##
## LEF for PtnCells ;
## created by Innovus v15.23-s045_1 on Mon Mar 16 21:43:37 2026
##

VERSION 5.8 ;

BUSBITCHARS "[]" ;
DIVIDERCHAR "/" ;

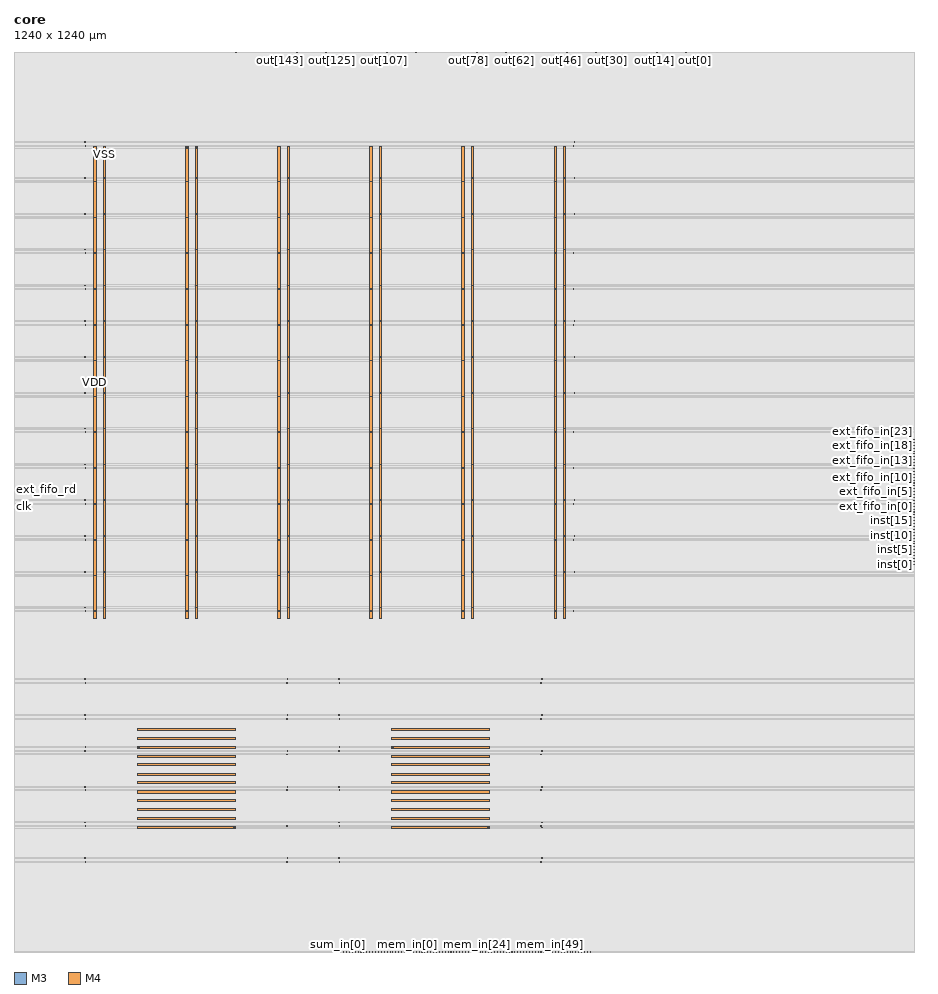
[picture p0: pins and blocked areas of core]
MACRO core
  CLASS BLOCK ;
  SIZE 1240.0000 BY 1240.0000 ;
  FOREIGN core 0.0000 0.0000 ;
  ORIGIN 0 0 ;
  SYMMETRY X Y R90 ;
  PIN clk
    DIRECTION INPUT ;
    USE SIGNAL ;
    PORT
      LAYER M3 ;
        RECT 0.0000 613.7500 0.5200 613.8500 ;
    END
  END clk
  PIN sum_in[23]
    DIRECTION INPUT ;
    USE SIGNAL ;
    PORT
      LAYER M4 ;
        RECT 538.0500 0.0000 538.1500 0.5200 ;
    END
  END sum_in[23]
  PIN sum_in[22]
    DIRECTION INPUT ;
    USE SIGNAL ;
    PORT
      LAYER M4 ;
        RECT 534.0500 0.0000 534.1500 0.5200 ;
    END
  END sum_in[22]
  PIN sum_in[21]
    DIRECTION INPUT ;
    USE SIGNAL ;
    PORT
      LAYER M4 ;
        RECT 530.0500 0.0000 530.1500 0.5200 ;
    END
  END sum_in[21]
  PIN sum_in[20]
    DIRECTION INPUT ;
    USE SIGNAL ;
    PORT
      LAYER M4 ;
        RECT 526.0500 0.0000 526.1500 0.5200 ;
    END
  END sum_in[20]
  PIN sum_in[19]
    DIRECTION INPUT ;
    USE SIGNAL ;
    PORT
      LAYER M4 ;
        RECT 522.0500 0.0000 522.1500 0.5200 ;
    END
  END sum_in[19]
  PIN sum_in[18]
    DIRECTION INPUT ;
    USE SIGNAL ;
    PORT
      LAYER M4 ;
        RECT 518.0500 0.0000 518.1500 0.5200 ;
    END
  END sum_in[18]
  PIN sum_in[17]
    DIRECTION INPUT ;
    USE SIGNAL ;
    PORT
      LAYER M4 ;
        RECT 514.0500 0.0000 514.1500 0.5200 ;
    END
  END sum_in[17]
  PIN sum_in[16]
    DIRECTION INPUT ;
    USE SIGNAL ;
    PORT
      LAYER M4 ;
        RECT 510.0500 0.0000 510.1500 0.5200 ;
    END
  END sum_in[16]
  PIN sum_in[15]
    DIRECTION INPUT ;
    USE SIGNAL ;
    PORT
      LAYER M4 ;
        RECT 506.0500 0.0000 506.1500 0.5200 ;
    END
  END sum_in[15]
  PIN sum_in[14]
    DIRECTION INPUT ;
    USE SIGNAL ;
    PORT
      LAYER M4 ;
        RECT 502.0500 0.0000 502.1500 0.5200 ;
    END
  END sum_in[14]
  PIN sum_in[13]
    DIRECTION INPUT ;
    USE SIGNAL ;
    PORT
      LAYER M4 ;
        RECT 498.0500 0.0000 498.1500 0.5200 ;
    END
  END sum_in[13]
  PIN sum_in[12]
    DIRECTION INPUT ;
    USE SIGNAL ;
    PORT
      LAYER M4 ;
        RECT 494.0500 0.0000 494.1500 0.5200 ;
    END
  END sum_in[12]
  PIN sum_in[11]
    DIRECTION INPUT ;
    USE SIGNAL ;
    PORT
      LAYER M4 ;
        RECT 490.0500 0.0000 490.1500 0.5200 ;
    END
  END sum_in[11]
  PIN sum_in[10]
    DIRECTION INPUT ;
    USE SIGNAL ;
    PORT
      LAYER M4 ;
        RECT 486.0500 0.0000 486.1500 0.5200 ;
    END
  END sum_in[10]
  PIN sum_in[9]
    DIRECTION INPUT ;
    USE SIGNAL ;
    PORT
      LAYER M4 ;
        RECT 482.0500 0.0000 482.1500 0.5200 ;
    END
  END sum_in[9]
  PIN sum_in[8]
    DIRECTION INPUT ;
    USE SIGNAL ;
    PORT
      LAYER M4 ;
        RECT 478.0500 0.0000 478.1500 0.5200 ;
    END
  END sum_in[8]
  PIN sum_in[7]
    DIRECTION INPUT ;
    USE SIGNAL ;
    PORT
      LAYER M4 ;
        RECT 474.0500 0.0000 474.1500 0.5200 ;
    END
  END sum_in[7]
  PIN sum_in[6]
    DIRECTION INPUT ;
    USE SIGNAL ;
    PORT
      LAYER M4 ;
        RECT 470.0500 0.0000 470.1500 0.5200 ;
    END
  END sum_in[6]
  PIN sum_in[5]
    DIRECTION INPUT ;
    USE SIGNAL ;
    PORT
      LAYER M4 ;
        RECT 466.0500 0.0000 466.1500 0.5200 ;
    END
  END sum_in[5]
  PIN sum_in[4]
    DIRECTION INPUT ;
    USE SIGNAL ;
    PORT
      LAYER M4 ;
        RECT 462.0500 0.0000 462.1500 0.5200 ;
    END
  END sum_in[4]
  PIN sum_in[3]
    DIRECTION INPUT ;
    USE SIGNAL ;
    PORT
      LAYER M4 ;
        RECT 458.0500 0.0000 458.1500 0.5200 ;
    END
  END sum_in[3]
  PIN sum_in[2]
    DIRECTION INPUT ;
    USE SIGNAL ;
    PORT
      LAYER M4 ;
        RECT 454.0500 0.0000 454.1500 0.5200 ;
    END
  END sum_in[2]
  PIN sum_in[1]
    DIRECTION INPUT ;
    USE SIGNAL ;
    PORT
      LAYER M4 ;
        RECT 450.0500 0.0000 450.1500 0.5200 ;
    END
  END sum_in[1]
  PIN sum_in[0]
    DIRECTION INPUT ;
    USE SIGNAL ;
    PORT
      LAYER M4 ;
        RECT 446.0500 0.0000 446.1500 0.5200 ;
    END
  END sum_in[0]
  PIN mem_in[63]
    DIRECTION INPUT ;
    USE SIGNAL ;
    PORT
      LAYER M4 ;
        RECT 794.0500 0.0000 794.1500 0.5200 ;
    END
  END mem_in[63]
  PIN mem_in[62]
    DIRECTION INPUT ;
    USE SIGNAL ;
    PORT
      LAYER M4 ;
        RECT 790.0500 0.0000 790.1500 0.5200 ;
    END
  END mem_in[62]
  PIN mem_in[61]
    DIRECTION INPUT ;
    USE SIGNAL ;
    PORT
      LAYER M4 ;
        RECT 786.0500 0.0000 786.1500 0.5200 ;
    END
  END mem_in[61]
  PIN mem_in[60]
    DIRECTION INPUT ;
    USE SIGNAL ;
    PORT
      LAYER M4 ;
        RECT 782.0500 0.0000 782.1500 0.5200 ;
    END
  END mem_in[60]
  PIN mem_in[59]
    DIRECTION INPUT ;
    USE SIGNAL ;
    PORT
      LAYER M4 ;
        RECT 778.0500 0.0000 778.1500 0.5200 ;
    END
  END mem_in[59]
  PIN mem_in[58]
    DIRECTION INPUT ;
    USE SIGNAL ;
    PORT
      LAYER M4 ;
        RECT 774.0500 0.0000 774.1500 0.5200 ;
    END
  END mem_in[58]
  PIN mem_in[57]
    DIRECTION INPUT ;
    USE SIGNAL ;
    PORT
      LAYER M4 ;
        RECT 770.0500 0.0000 770.1500 0.5200 ;
    END
  END mem_in[57]
  PIN mem_in[56]
    DIRECTION INPUT ;
    USE SIGNAL ;
    PORT
      LAYER M4 ;
        RECT 766.0500 0.0000 766.1500 0.5200 ;
    END
  END mem_in[56]
  PIN mem_in[55]
    DIRECTION INPUT ;
    USE SIGNAL ;
    PORT
      LAYER M4 ;
        RECT 762.0500 0.0000 762.1500 0.5200 ;
    END
  END mem_in[55]
  PIN mem_in[54]
    DIRECTION INPUT ;
    USE SIGNAL ;
    PORT
      LAYER M4 ;
        RECT 758.0500 0.0000 758.1500 0.5200 ;
    END
  END mem_in[54]
  PIN mem_in[53]
    DIRECTION INPUT ;
    USE SIGNAL ;
    PORT
      LAYER M4 ;
        RECT 754.0500 0.0000 754.1500 0.5200 ;
    END
  END mem_in[53]
  PIN mem_in[52]
    DIRECTION INPUT ;
    USE SIGNAL ;
    PORT
      LAYER M4 ;
        RECT 750.0500 0.0000 750.1500 0.5200 ;
    END
  END mem_in[52]
  PIN mem_in[51]
    DIRECTION INPUT ;
    USE SIGNAL ;
    PORT
      LAYER M4 ;
        RECT 746.0500 0.0000 746.1500 0.5200 ;
    END
  END mem_in[51]
  PIN mem_in[50]
    DIRECTION INPUT ;
    USE SIGNAL ;
    PORT
      LAYER M4 ;
        RECT 742.0500 0.0000 742.1500 0.5200 ;
    END
  END mem_in[50]
  PIN mem_in[49]
    DIRECTION INPUT ;
    USE SIGNAL ;
    PORT
      LAYER M4 ;
        RECT 738.0500 0.0000 738.1500 0.5200 ;
    END
  END mem_in[49]
  PIN mem_in[48]
    DIRECTION INPUT ;
    USE SIGNAL ;
    PORT
      LAYER M4 ;
        RECT 734.0500 0.0000 734.1500 0.5200 ;
    END
  END mem_in[48]
  PIN mem_in[47]
    DIRECTION INPUT ;
    USE SIGNAL ;
    PORT
      LAYER M4 ;
        RECT 730.0500 0.0000 730.1500 0.5200 ;
    END
  END mem_in[47]
  PIN mem_in[46]
    DIRECTION INPUT ;
    USE SIGNAL ;
    PORT
      LAYER M4 ;
        RECT 726.0500 0.0000 726.1500 0.5200 ;
    END
  END mem_in[46]
  PIN mem_in[45]
    DIRECTION INPUT ;
    USE SIGNAL ;
    PORT
      LAYER M4 ;
        RECT 722.0500 0.0000 722.1500 0.5200 ;
    END
  END mem_in[45]
  PIN mem_in[44]
    DIRECTION INPUT ;
    USE SIGNAL ;
    PORT
      LAYER M4 ;
        RECT 718.0500 0.0000 718.1500 0.5200 ;
    END
  END mem_in[44]
  PIN mem_in[43]
    DIRECTION INPUT ;
    USE SIGNAL ;
    PORT
      LAYER M4 ;
        RECT 714.0500 0.0000 714.1500 0.5200 ;
    END
  END mem_in[43]
  PIN mem_in[42]
    DIRECTION INPUT ;
    USE SIGNAL ;
    PORT
      LAYER M4 ;
        RECT 710.0500 0.0000 710.1500 0.5200 ;
    END
  END mem_in[42]
  PIN mem_in[41]
    DIRECTION INPUT ;
    USE SIGNAL ;
    PORT
      LAYER M4 ;
        RECT 706.0500 0.0000 706.1500 0.5200 ;
    END
  END mem_in[41]
  PIN mem_in[40]
    DIRECTION INPUT ;
    USE SIGNAL ;
    PORT
      LAYER M4 ;
        RECT 702.0500 0.0000 702.1500 0.5200 ;
    END
  END mem_in[40]
  PIN mem_in[39]
    DIRECTION INPUT ;
    USE SIGNAL ;
    PORT
      LAYER M4 ;
        RECT 698.0500 0.0000 698.1500 0.5200 ;
    END
  END mem_in[39]
  PIN mem_in[38]
    DIRECTION INPUT ;
    USE SIGNAL ;
    PORT
      LAYER M4 ;
        RECT 694.0500 0.0000 694.1500 0.5200 ;
    END
  END mem_in[38]
  PIN mem_in[37]
    DIRECTION INPUT ;
    USE SIGNAL ;
    PORT
      LAYER M4 ;
        RECT 690.0500 0.0000 690.1500 0.5200 ;
    END
  END mem_in[37]
  PIN mem_in[36]
    DIRECTION INPUT ;
    USE SIGNAL ;
    PORT
      LAYER M4 ;
        RECT 686.0500 0.0000 686.1500 0.5200 ;
    END
  END mem_in[36]
  PIN mem_in[35]
    DIRECTION INPUT ;
    USE SIGNAL ;
    PORT
      LAYER M4 ;
        RECT 682.0500 0.0000 682.1500 0.5200 ;
    END
  END mem_in[35]
  PIN mem_in[34]
    DIRECTION INPUT ;
    USE SIGNAL ;
    PORT
      LAYER M4 ;
        RECT 678.0500 0.0000 678.1500 0.5200 ;
    END
  END mem_in[34]
  PIN mem_in[33]
    DIRECTION INPUT ;
    USE SIGNAL ;
    PORT
      LAYER M4 ;
        RECT 674.0500 0.0000 674.1500 0.5200 ;
    END
  END mem_in[33]
  PIN mem_in[32]
    DIRECTION INPUT ;
    USE SIGNAL ;
    PORT
      LAYER M4 ;
        RECT 670.0500 0.0000 670.1500 0.5200 ;
    END
  END mem_in[32]
  PIN mem_in[31]
    DIRECTION INPUT ;
    USE SIGNAL ;
    PORT
      LAYER M4 ;
        RECT 666.0500 0.0000 666.1500 0.5200 ;
    END
  END mem_in[31]
  PIN mem_in[30]
    DIRECTION INPUT ;
    USE SIGNAL ;
    PORT
      LAYER M4 ;
        RECT 662.0500 0.0000 662.1500 0.5200 ;
    END
  END mem_in[30]
  PIN mem_in[29]
    DIRECTION INPUT ;
    USE SIGNAL ;
    PORT
      LAYER M4 ;
        RECT 658.0500 0.0000 658.1500 0.5200 ;
    END
  END mem_in[29]
  PIN mem_in[28]
    DIRECTION INPUT ;
    USE SIGNAL ;
    PORT
      LAYER M4 ;
        RECT 654.0500 0.0000 654.1500 0.5200 ;
    END
  END mem_in[28]
  PIN mem_in[27]
    DIRECTION INPUT ;
    USE SIGNAL ;
    PORT
      LAYER M4 ;
        RECT 650.0500 0.0000 650.1500 0.5200 ;
    END
  END mem_in[27]
  PIN mem_in[26]
    DIRECTION INPUT ;
    USE SIGNAL ;
    PORT
      LAYER M4 ;
        RECT 646.0500 0.0000 646.1500 0.5200 ;
    END
  END mem_in[26]
  PIN mem_in[25]
    DIRECTION INPUT ;
    USE SIGNAL ;
    PORT
      LAYER M4 ;
        RECT 642.0500 0.0000 642.1500 0.5200 ;
    END
  END mem_in[25]
  PIN mem_in[24]
    DIRECTION INPUT ;
    USE SIGNAL ;
    PORT
      LAYER M4 ;
        RECT 638.0500 0.0000 638.1500 0.5200 ;
    END
  END mem_in[24]
  PIN mem_in[23]
    DIRECTION INPUT ;
    USE SIGNAL ;
    PORT
      LAYER M4 ;
        RECT 634.0500 0.0000 634.1500 0.5200 ;
    END
  END mem_in[23]
  PIN mem_in[22]
    DIRECTION INPUT ;
    USE SIGNAL ;
    PORT
      LAYER M4 ;
        RECT 630.0500 0.0000 630.1500 0.5200 ;
    END
  END mem_in[22]
  PIN mem_in[21]
    DIRECTION INPUT ;
    USE SIGNAL ;
    PORT
      LAYER M4 ;
        RECT 626.0500 0.0000 626.1500 0.5200 ;
    END
  END mem_in[21]
  PIN mem_in[20]
    DIRECTION INPUT ;
    USE SIGNAL ;
    PORT
      LAYER M4 ;
        RECT 622.0500 0.0000 622.1500 0.5200 ;
    END
  END mem_in[20]
  PIN mem_in[19]
    DIRECTION INPUT ;
    USE SIGNAL ;
    PORT
      LAYER M4 ;
        RECT 618.0500 0.0000 618.1500 0.5200 ;
    END
  END mem_in[19]
  PIN mem_in[18]
    DIRECTION INPUT ;
    USE SIGNAL ;
    PORT
      LAYER M4 ;
        RECT 614.0500 0.0000 614.1500 0.5200 ;
    END
  END mem_in[18]
  PIN mem_in[17]
    DIRECTION INPUT ;
    USE SIGNAL ;
    PORT
      LAYER M4 ;
        RECT 610.0500 0.0000 610.1500 0.5200 ;
    END
  END mem_in[17]
  PIN mem_in[16]
    DIRECTION INPUT ;
    USE SIGNAL ;
    PORT
      LAYER M4 ;
        RECT 606.0500 0.0000 606.1500 0.5200 ;
    END
  END mem_in[16]
  PIN mem_in[15]
    DIRECTION INPUT ;
    USE SIGNAL ;
    PORT
      LAYER M4 ;
        RECT 602.0500 0.0000 602.1500 0.5200 ;
    END
  END mem_in[15]
  PIN mem_in[14]
    DIRECTION INPUT ;
    USE SIGNAL ;
    PORT
      LAYER M4 ;
        RECT 598.0500 0.0000 598.1500 0.5200 ;
    END
  END mem_in[14]
  PIN mem_in[13]
    DIRECTION INPUT ;
    USE SIGNAL ;
    PORT
      LAYER M4 ;
        RECT 594.0500 0.0000 594.1500 0.5200 ;
    END
  END mem_in[13]
  PIN mem_in[12]
    DIRECTION INPUT ;
    USE SIGNAL ;
    PORT
      LAYER M4 ;
        RECT 590.0500 0.0000 590.1500 0.5200 ;
    END
  END mem_in[12]
  PIN mem_in[11]
    DIRECTION INPUT ;
    USE SIGNAL ;
    PORT
      LAYER M4 ;
        RECT 586.0500 0.0000 586.1500 0.5200 ;
    END
  END mem_in[11]
  PIN mem_in[10]
    DIRECTION INPUT ;
    USE SIGNAL ;
    PORT
      LAYER M4 ;
        RECT 582.0500 0.0000 582.1500 0.5200 ;
    END
  END mem_in[10]
  PIN mem_in[9]
    DIRECTION INPUT ;
    USE SIGNAL ;
    PORT
      LAYER M4 ;
        RECT 578.0500 0.0000 578.1500 0.5200 ;
    END
  END mem_in[9]
  PIN mem_in[8]
    DIRECTION INPUT ;
    USE SIGNAL ;
    PORT
      LAYER M4 ;
        RECT 574.0500 0.0000 574.1500 0.5200 ;
    END
  END mem_in[8]
  PIN mem_in[7]
    DIRECTION INPUT ;
    USE SIGNAL ;
    PORT
      LAYER M4 ;
        RECT 570.0500 0.0000 570.1500 0.5200 ;
    END
  END mem_in[7]
  PIN mem_in[6]
    DIRECTION INPUT ;
    USE SIGNAL ;
    PORT
      LAYER M4 ;
        RECT 566.0500 0.0000 566.1500 0.5200 ;
    END
  END mem_in[6]
  PIN mem_in[5]
    DIRECTION INPUT ;
    USE SIGNAL ;
    PORT
      LAYER M4 ;
        RECT 562.0500 0.0000 562.1500 0.5200 ;
    END
  END mem_in[5]
  PIN mem_in[4]
    DIRECTION INPUT ;
    USE SIGNAL ;
    PORT
      LAYER M4 ;
        RECT 558.0500 0.0000 558.1500 0.5200 ;
    END
  END mem_in[4]
  PIN mem_in[3]
    DIRECTION INPUT ;
    USE SIGNAL ;
    PORT
      LAYER M4 ;
        RECT 554.0500 0.0000 554.1500 0.5200 ;
    END
  END mem_in[3]
  PIN mem_in[2]
    DIRECTION INPUT ;
    USE SIGNAL ;
    PORT
      LAYER M4 ;
        RECT 550.0500 0.0000 550.1500 0.5200 ;
    END
  END mem_in[2]
  PIN mem_in[1]
    DIRECTION INPUT ;
    USE SIGNAL ;
    PORT
      LAYER M4 ;
        RECT 546.0500 0.0000 546.1500 0.5200 ;
    END
  END mem_in[1]
  PIN mem_in[0]
    DIRECTION INPUT ;
    USE SIGNAL ;
    PORT
      LAYER M4 ;
        RECT 542.0500 0.0000 542.1500 0.5200 ;
    END
  END mem_in[0]
  PIN out[159]
    DIRECTION OUTPUT ;
    USE SIGNAL ;
    PORT
      LAYER M4 ;
        RECT 301.8500 1239.4800 301.9500 1240.0000 ;
    END
  END out[159]
  PIN out[158]
    DIRECTION OUTPUT ;
    USE SIGNAL ;
    PORT
      LAYER M4 ;
        RECT 305.8500 1239.4800 305.9500 1240.0000 ;
    END
  END out[158]
  PIN out[157]
    DIRECTION OUTPUT ;
    USE SIGNAL ;
    PORT
      LAYER M4 ;
        RECT 309.8500 1239.4800 309.9500 1240.0000 ;
    END
  END out[157]
  PIN out[156]
    DIRECTION OUTPUT ;
    USE SIGNAL ;
    PORT
      LAYER M4 ;
        RECT 313.8500 1239.4800 313.9500 1240.0000 ;
    END
  END out[156]
  PIN out[155]
    DIRECTION OUTPUT ;
    USE SIGNAL ;
    PORT
      LAYER M4 ;
        RECT 317.8500 1239.4800 317.9500 1240.0000 ;
    END
  END out[155]
  PIN out[154]
    DIRECTION OUTPUT ;
    USE SIGNAL ;
    PORT
      LAYER M4 ;
        RECT 321.8500 1239.4800 321.9500 1240.0000 ;
    END
  END out[154]
  PIN out[153]
    DIRECTION OUTPUT ;
    USE SIGNAL ;
    PORT
      LAYER M4 ;
        RECT 325.8500 1239.4800 325.9500 1240.0000 ;
    END
  END out[153]
  PIN out[152]
    DIRECTION OUTPUT ;
    USE SIGNAL ;
    PORT
      LAYER M4 ;
        RECT 329.8500 1239.4800 329.9500 1240.0000 ;
    END
  END out[152]
  PIN out[151]
    DIRECTION OUTPUT ;
    USE SIGNAL ;
    PORT
      LAYER M4 ;
        RECT 333.8500 1239.4800 333.9500 1240.0000 ;
    END
  END out[151]
  PIN out[150]
    DIRECTION OUTPUT ;
    USE SIGNAL ;
    PORT
      LAYER M4 ;
        RECT 337.8500 1239.4800 337.9500 1240.0000 ;
    END
  END out[150]
  PIN out[149]
    DIRECTION OUTPUT ;
    USE SIGNAL ;
    PORT
      LAYER M4 ;
        RECT 341.8500 1239.4800 341.9500 1240.0000 ;
    END
  END out[149]
  PIN out[148]
    DIRECTION OUTPUT ;
    USE SIGNAL ;
    PORT
      LAYER M4 ;
        RECT 345.8500 1239.4800 345.9500 1240.0000 ;
    END
  END out[148]
  PIN out[147]
    DIRECTION OUTPUT ;
    USE SIGNAL ;
    PORT
      LAYER M4 ;
        RECT 349.8500 1239.4800 349.9500 1240.0000 ;
    END
  END out[147]
  PIN out[146]
    DIRECTION OUTPUT ;
    USE SIGNAL ;
    PORT
      LAYER M4 ;
        RECT 353.8500 1239.4800 353.9500 1240.0000 ;
    END
  END out[146]
  PIN out[145]
    DIRECTION OUTPUT ;
    USE SIGNAL ;
    PORT
      LAYER M4 ;
        RECT 357.8500 1239.4800 357.9500 1240.0000 ;
    END
  END out[145]
  PIN out[144]
    DIRECTION OUTPUT ;
    USE SIGNAL ;
    PORT
      LAYER M4 ;
        RECT 361.8500 1239.4800 361.9500 1240.0000 ;
    END
  END out[144]
  PIN out[143]
    DIRECTION OUTPUT ;
    USE SIGNAL ;
    PORT
      LAYER M4 ;
        RECT 365.8500 1239.4800 365.9500 1240.0000 ;
    END
  END out[143]
  PIN out[142]
    DIRECTION OUTPUT ;
    USE SIGNAL ;
    PORT
      LAYER M4 ;
        RECT 369.8500 1239.4800 369.9500 1240.0000 ;
    END
  END out[142]
  PIN out[141]
    DIRECTION OUTPUT ;
    USE SIGNAL ;
    PORT
      LAYER M4 ;
        RECT 373.8500 1239.4800 373.9500 1240.0000 ;
    END
  END out[141]
  PIN out[140]
    DIRECTION OUTPUT ;
    USE SIGNAL ;
    PORT
      LAYER M4 ;
        RECT 377.8500 1239.4800 377.9500 1240.0000 ;
    END
  END out[140]
  PIN out[139]
    DIRECTION OUTPUT ;
    USE SIGNAL ;
    PORT
      LAYER M4 ;
        RECT 381.8500 1239.4800 381.9500 1240.0000 ;
    END
  END out[139]
  PIN out[138]
    DIRECTION OUTPUT ;
    USE SIGNAL ;
    PORT
      LAYER M4 ;
        RECT 385.8500 1239.4800 385.9500 1240.0000 ;
    END
  END out[138]
  PIN out[137]
    DIRECTION OUTPUT ;
    USE SIGNAL ;
    PORT
      LAYER M4 ;
        RECT 389.8500 1239.4800 389.9500 1240.0000 ;
    END
  END out[137]
  PIN out[136]
    DIRECTION OUTPUT ;
    USE SIGNAL ;
    PORT
      LAYER M4 ;
        RECT 393.8500 1239.4800 393.9500 1240.0000 ;
    END
  END out[136]
  PIN out[135]
    DIRECTION OUTPUT ;
    USE SIGNAL ;
    PORT
      LAYER M4 ;
        RECT 397.8500 1239.4800 397.9500 1240.0000 ;
    END
  END out[135]
  PIN out[134]
    DIRECTION OUTPUT ;
    USE SIGNAL ;
    PORT
      LAYER M4 ;
        RECT 401.8500 1239.4800 401.9500 1240.0000 ;
    END
  END out[134]
  PIN out[133]
    DIRECTION OUTPUT ;
    USE SIGNAL ;
    PORT
      LAYER M4 ;
        RECT 405.8500 1239.4800 405.9500 1240.0000 ;
    END
  END out[133]
  PIN out[132]
    DIRECTION OUTPUT ;
    USE SIGNAL ;
    PORT
      LAYER M4 ;
        RECT 409.8500 1239.4800 409.9500 1240.0000 ;
    END
  END out[132]
  PIN out[131]
    DIRECTION OUTPUT ;
    USE SIGNAL ;
    PORT
      LAYER M4 ;
        RECT 413.8500 1239.4800 413.9500 1240.0000 ;
    END
  END out[131]
  PIN out[130]
    DIRECTION OUTPUT ;
    USE SIGNAL ;
    PORT
      LAYER M4 ;
        RECT 417.8500 1239.4800 417.9500 1240.0000 ;
    END
  END out[130]
  PIN out[129]
    DIRECTION OUTPUT ;
    USE SIGNAL ;
    PORT
      LAYER M4 ;
        RECT 421.8500 1239.4800 421.9500 1240.0000 ;
    END
  END out[129]
  PIN out[128]
    DIRECTION OUTPUT ;
    USE SIGNAL ;
    PORT
      LAYER M4 ;
        RECT 425.8500 1239.4800 425.9500 1240.0000 ;
    END
  END out[128]
  PIN out[127]
    DIRECTION OUTPUT ;
    USE SIGNAL ;
    PORT
      LAYER M4 ;
        RECT 429.8500 1239.4800 429.9500 1240.0000 ;
    END
  END out[127]
  PIN out[126]
    DIRECTION OUTPUT ;
    USE SIGNAL ;
    PORT
      LAYER M4 ;
        RECT 433.8500 1239.4800 433.9500 1240.0000 ;
    END
  END out[126]
  PIN out[125]
    DIRECTION OUTPUT ;
    USE SIGNAL ;
    PORT
      LAYER M4 ;
        RECT 437.8500 1239.4800 437.9500 1240.0000 ;
    END
  END out[125]
  PIN out[124]
    DIRECTION OUTPUT ;
    USE SIGNAL ;
    PORT
      LAYER M4 ;
        RECT 441.8500 1239.4800 441.9500 1240.0000 ;
    END
  END out[124]
  PIN out[123]
    DIRECTION OUTPUT ;
    USE SIGNAL ;
    PORT
      LAYER M4 ;
        RECT 445.8500 1239.4800 445.9500 1240.0000 ;
    END
  END out[123]
  PIN out[122]
    DIRECTION OUTPUT ;
    USE SIGNAL ;
    PORT
      LAYER M4 ;
        RECT 449.8500 1239.4800 449.9500 1240.0000 ;
    END
  END out[122]
  PIN out[121]
    DIRECTION OUTPUT ;
    USE SIGNAL ;
    PORT
      LAYER M4 ;
        RECT 453.8500 1239.4800 453.9500 1240.0000 ;
    END
  END out[121]
  PIN out[120]
    DIRECTION OUTPUT ;
    USE SIGNAL ;
    PORT
      LAYER M4 ;
        RECT 457.8500 1239.4800 457.9500 1240.0000 ;
    END
  END out[120]
  PIN out[119]
    DIRECTION OUTPUT ;
    USE SIGNAL ;
    PORT
      LAYER M4 ;
        RECT 461.8500 1239.4800 461.9500 1240.0000 ;
    END
  END out[119]
  PIN out[118]
    DIRECTION OUTPUT ;
    USE SIGNAL ;
    PORT
      LAYER M4 ;
        RECT 465.8500 1239.4800 465.9500 1240.0000 ;
    END
  END out[118]
  PIN out[117]
    DIRECTION OUTPUT ;
    USE SIGNAL ;
    PORT
      LAYER M4 ;
        RECT 469.8500 1239.4800 469.9500 1240.0000 ;
    END
  END out[117]
  PIN out[116]
    DIRECTION OUTPUT ;
    USE SIGNAL ;
    PORT
      LAYER M4 ;
        RECT 473.8500 1239.4800 473.9500 1240.0000 ;
    END
  END out[116]
  PIN out[115]
    DIRECTION OUTPUT ;
    USE SIGNAL ;
    PORT
      LAYER M4 ;
        RECT 477.8500 1239.4800 477.9500 1240.0000 ;
    END
  END out[115]
  PIN out[114]
    DIRECTION OUTPUT ;
    USE SIGNAL ;
    PORT
      LAYER M4 ;
        RECT 481.8500 1239.4800 481.9500 1240.0000 ;
    END
  END out[114]
  PIN out[113]
    DIRECTION OUTPUT ;
    USE SIGNAL ;
    PORT
      LAYER M4 ;
        RECT 485.8500 1239.4800 485.9500 1240.0000 ;
    END
  END out[113]
  PIN out[112]
    DIRECTION OUTPUT ;
    USE SIGNAL ;
    PORT
      LAYER M4 ;
        RECT 489.8500 1239.4800 489.9500 1240.0000 ;
    END
  END out[112]
  PIN out[111]
    DIRECTION OUTPUT ;
    USE SIGNAL ;
    PORT
      LAYER M4 ;
        RECT 493.8500 1239.4800 493.9500 1240.0000 ;
    END
  END out[111]
  PIN out[110]
    DIRECTION OUTPUT ;
    USE SIGNAL ;
    PORT
      LAYER M4 ;
        RECT 497.8500 1239.4800 497.9500 1240.0000 ;
    END
  END out[110]
  PIN out[109]
    DIRECTION OUTPUT ;
    USE SIGNAL ;
    PORT
      LAYER M4 ;
        RECT 501.8500 1239.4800 501.9500 1240.0000 ;
    END
  END out[109]
  PIN out[108]
    DIRECTION OUTPUT ;
    USE SIGNAL ;
    PORT
      LAYER M4 ;
        RECT 505.8500 1239.4800 505.9500 1240.0000 ;
    END
  END out[108]
  PIN out[107]
    DIRECTION OUTPUT ;
    USE SIGNAL ;
    PORT
      LAYER M4 ;
        RECT 509.8500 1239.4800 509.9500 1240.0000 ;
    END
  END out[107]
  PIN out[106]
    DIRECTION OUTPUT ;
    USE SIGNAL ;
    PORT
      LAYER M4 ;
        RECT 513.8500 1239.4800 513.9500 1240.0000 ;
    END
  END out[106]
  PIN out[105]
    DIRECTION OUTPUT ;
    USE SIGNAL ;
    PORT
      LAYER M4 ;
        RECT 517.8500 1239.4800 517.9500 1240.0000 ;
    END
  END out[105]
  PIN out[104]
    DIRECTION OUTPUT ;
    USE SIGNAL ;
    PORT
      LAYER M4 ;
        RECT 521.8500 1239.4800 521.9500 1240.0000 ;
    END
  END out[104]
  PIN out[103]
    DIRECTION OUTPUT ;
    USE SIGNAL ;
    PORT
      LAYER M4 ;
        RECT 525.8500 1239.4800 525.9500 1240.0000 ;
    END
  END out[103]
  PIN out[102]
    DIRECTION OUTPUT ;
    USE SIGNAL ;
    PORT
      LAYER M4 ;
        RECT 529.8500 1239.4800 529.9500 1240.0000 ;
    END
  END out[102]
  PIN out[101]
    DIRECTION OUTPUT ;
    USE SIGNAL ;
    PORT
      LAYER M4 ;
        RECT 533.8500 1239.4800 533.9500 1240.0000 ;
    END
  END out[101]
  PIN out[100]
    DIRECTION OUTPUT ;
    USE SIGNAL ;
    PORT
      LAYER M4 ;
        RECT 537.8500 1239.4800 537.9500 1240.0000 ;
    END
  END out[100]
  PIN out[99]
    DIRECTION OUTPUT ;
    USE SIGNAL ;
    PORT
      LAYER M4 ;
        RECT 541.8500 1239.4800 541.9500 1240.0000 ;
    END
  END out[99]
  PIN out[98]
    DIRECTION OUTPUT ;
    USE SIGNAL ;
    PORT
      LAYER M4 ;
        RECT 545.8500 1239.4800 545.9500 1240.0000 ;
    END
  END out[98]
  PIN out[97]
    DIRECTION OUTPUT ;
    USE SIGNAL ;
    PORT
      LAYER M4 ;
        RECT 549.8500 1239.4800 549.9500 1240.0000 ;
    END
  END out[97]
  PIN out[96]
    DIRECTION OUTPUT ;
    USE SIGNAL ;
    PORT
      LAYER M4 ;
        RECT 553.8500 1239.4800 553.9500 1240.0000 ;
    END
  END out[96]
  PIN out[95]
    DIRECTION OUTPUT ;
    USE SIGNAL ;
    PORT
      LAYER M4 ;
        RECT 557.8500 1239.4800 557.9500 1240.0000 ;
    END
  END out[95]
  PIN out[94]
    DIRECTION OUTPUT ;
    USE SIGNAL ;
    PORT
      LAYER M4 ;
        RECT 561.8500 1239.4800 561.9500 1240.0000 ;
    END
  END out[94]
  PIN out[93]
    DIRECTION OUTPUT ;
    USE SIGNAL ;
    PORT
      LAYER M4 ;
        RECT 565.8500 1239.4800 565.9500 1240.0000 ;
    END
  END out[93]
  PIN out[92]
    DIRECTION OUTPUT ;
    USE SIGNAL ;
    PORT
      LAYER M4 ;
        RECT 569.8500 1239.4800 569.9500 1240.0000 ;
    END
  END out[92]
  PIN out[91]
    DIRECTION OUTPUT ;
    USE SIGNAL ;
    PORT
      LAYER M4 ;
        RECT 573.8500 1239.4800 573.9500 1240.0000 ;
    END
  END out[91]
  PIN out[90]
    DIRECTION OUTPUT ;
    USE SIGNAL ;
    PORT
      LAYER M4 ;
        RECT 577.8500 1239.4800 577.9500 1240.0000 ;
    END
  END out[90]
  PIN out[89]
    DIRECTION OUTPUT ;
    USE SIGNAL ;
    PORT
      LAYER M4 ;
        RECT 581.8500 1239.4800 581.9500 1240.0000 ;
    END
  END out[89]
  PIN out[88]
    DIRECTION OUTPUT ;
    USE SIGNAL ;
    PORT
      LAYER M4 ;
        RECT 585.8500 1239.4800 585.9500 1240.0000 ;
    END
  END out[88]
  PIN out[87]
    DIRECTION OUTPUT ;
    USE SIGNAL ;
    PORT
      LAYER M4 ;
        RECT 589.8500 1239.4800 589.9500 1240.0000 ;
    END
  END out[87]
  PIN out[86]
    DIRECTION OUTPUT ;
    USE SIGNAL ;
    PORT
      LAYER M4 ;
        RECT 593.8500 1239.4800 593.9500 1240.0000 ;
    END
  END out[86]
  PIN out[85]
    DIRECTION OUTPUT ;
    USE SIGNAL ;
    PORT
      LAYER M4 ;
        RECT 597.8500 1239.4800 597.9500 1240.0000 ;
    END
  END out[85]
  PIN out[84]
    DIRECTION OUTPUT ;
    USE SIGNAL ;
    PORT
      LAYER M4 ;
        RECT 601.8500 1239.4800 601.9500 1240.0000 ;
    END
  END out[84]
  PIN out[83]
    DIRECTION OUTPUT ;
    USE SIGNAL ;
    PORT
      LAYER M4 ;
        RECT 605.8500 1239.4800 605.9500 1240.0000 ;
    END
  END out[83]
  PIN out[82]
    DIRECTION OUTPUT ;
    USE SIGNAL ;
    PORT
      LAYER M4 ;
        RECT 609.8500 1239.4800 609.9500 1240.0000 ;
    END
  END out[82]
  PIN out[81]
    DIRECTION OUTPUT ;
    USE SIGNAL ;
    PORT
      LAYER M4 ;
        RECT 613.8500 1239.4800 613.9500 1240.0000 ;
    END
  END out[81]
  PIN out[80]
    DIRECTION OUTPUT ;
    USE SIGNAL ;
    PORT
      LAYER M4 ;
        RECT 617.8500 1239.4800 617.9500 1240.0000 ;
    END
  END out[80]
  PIN out[79]
    DIRECTION OUTPUT ;
    USE SIGNAL ;
    PORT
      LAYER M4 ;
        RECT 621.8500 1239.4800 621.9500 1240.0000 ;
    END
  END out[79]
  PIN out[78]
    DIRECTION OUTPUT ;
    USE SIGNAL ;
    PORT
      LAYER M4 ;
        RECT 625.8500 1239.4800 625.9500 1240.0000 ;
    END
  END out[78]
  PIN out[77]
    DIRECTION OUTPUT ;
    USE SIGNAL ;
    PORT
      LAYER M4 ;
        RECT 629.8500 1239.4800 629.9500 1240.0000 ;
    END
  END out[77]
  PIN out[76]
    DIRECTION OUTPUT ;
    USE SIGNAL ;
    PORT
      LAYER M4 ;
        RECT 633.8500 1239.4800 633.9500 1240.0000 ;
    END
  END out[76]
  PIN out[75]
    DIRECTION OUTPUT ;
    USE SIGNAL ;
    PORT
      LAYER M4 ;
        RECT 637.8500 1239.4800 637.9500 1240.0000 ;
    END
  END out[75]
  PIN out[74]
    DIRECTION OUTPUT ;
    USE SIGNAL ;
    PORT
      LAYER M4 ;
        RECT 641.8500 1239.4800 641.9500 1240.0000 ;
    END
  END out[74]
  PIN out[73]
    DIRECTION OUTPUT ;
    USE SIGNAL ;
    PORT
      LAYER M4 ;
        RECT 645.8500 1239.4800 645.9500 1240.0000 ;
    END
  END out[73]
  PIN out[72]
    DIRECTION OUTPUT ;
    USE SIGNAL ;
    PORT
      LAYER M4 ;
        RECT 649.8500 1239.4800 649.9500 1240.0000 ;
    END
  END out[72]
  PIN out[71]
    DIRECTION OUTPUT ;
    USE SIGNAL ;
    PORT
      LAYER M4 ;
        RECT 653.8500 1239.4800 653.9500 1240.0000 ;
    END
  END out[71]
  PIN out[70]
    DIRECTION OUTPUT ;
    USE SIGNAL ;
    PORT
      LAYER M4 ;
        RECT 657.8500 1239.4800 657.9500 1240.0000 ;
    END
  END out[70]
  PIN out[69]
    DIRECTION OUTPUT ;
    USE SIGNAL ;
    PORT
      LAYER M4 ;
        RECT 661.8500 1239.4800 661.9500 1240.0000 ;
    END
  END out[69]
  PIN out[68]
    DIRECTION OUTPUT ;
    USE SIGNAL ;
    PORT
      LAYER M4 ;
        RECT 665.8500 1239.4800 665.9500 1240.0000 ;
    END
  END out[68]
  PIN out[67]
    DIRECTION OUTPUT ;
    USE SIGNAL ;
    PORT
      LAYER M4 ;
        RECT 669.8500 1239.4800 669.9500 1240.0000 ;
    END
  END out[67]
  PIN out[66]
    DIRECTION OUTPUT ;
    USE SIGNAL ;
    PORT
      LAYER M4 ;
        RECT 673.8500 1239.4800 673.9500 1240.0000 ;
    END
  END out[66]
  PIN out[65]
    DIRECTION OUTPUT ;
    USE SIGNAL ;
    PORT
      LAYER M4 ;
        RECT 677.8500 1239.4800 677.9500 1240.0000 ;
    END
  END out[65]
  PIN out[64]
    DIRECTION OUTPUT ;
    USE SIGNAL ;
    PORT
      LAYER M4 ;
        RECT 681.8500 1239.4800 681.9500 1240.0000 ;
    END
  END out[64]
  PIN out[63]
    DIRECTION OUTPUT ;
    USE SIGNAL ;
    PORT
      LAYER M4 ;
        RECT 685.8500 1239.4800 685.9500 1240.0000 ;
    END
  END out[63]
  PIN out[62]
    DIRECTION OUTPUT ;
    USE SIGNAL ;
    PORT
      LAYER M4 ;
        RECT 689.8500 1239.4800 689.9500 1240.0000 ;
    END
  END out[62]
  PIN out[61]
    DIRECTION OUTPUT ;
    USE SIGNAL ;
    PORT
      LAYER M4 ;
        RECT 693.8500 1239.4800 693.9500 1240.0000 ;
    END
  END out[61]
  PIN out[60]
    DIRECTION OUTPUT ;
    USE SIGNAL ;
    PORT
      LAYER M4 ;
        RECT 697.8500 1239.4800 697.9500 1240.0000 ;
    END
  END out[60]
  PIN out[59]
    DIRECTION OUTPUT ;
    USE SIGNAL ;
    PORT
      LAYER M4 ;
        RECT 701.8500 1239.4800 701.9500 1240.0000 ;
    END
  END out[59]
  PIN out[58]
    DIRECTION OUTPUT ;
    USE SIGNAL ;
    PORT
      LAYER M4 ;
        RECT 705.8500 1239.4800 705.9500 1240.0000 ;
    END
  END out[58]
  PIN out[57]
    DIRECTION OUTPUT ;
    USE SIGNAL ;
    PORT
      LAYER M4 ;
        RECT 709.8500 1239.4800 709.9500 1240.0000 ;
    END
  END out[57]
  PIN out[56]
    DIRECTION OUTPUT ;
    USE SIGNAL ;
    PORT
      LAYER M4 ;
        RECT 713.8500 1239.4800 713.9500 1240.0000 ;
    END
  END out[56]
  PIN out[55]
    DIRECTION OUTPUT ;
    USE SIGNAL ;
    PORT
      LAYER M4 ;
        RECT 717.8500 1239.4800 717.9500 1240.0000 ;
    END
  END out[55]
  PIN out[54]
    DIRECTION OUTPUT ;
    USE SIGNAL ;
    PORT
      LAYER M4 ;
        RECT 721.8500 1239.4800 721.9500 1240.0000 ;
    END
  END out[54]
  PIN out[53]
    DIRECTION OUTPUT ;
    USE SIGNAL ;
    PORT
      LAYER M4 ;
        RECT 725.8500 1239.4800 725.9500 1240.0000 ;
    END
  END out[53]
  PIN out[52]
    DIRECTION OUTPUT ;
    USE SIGNAL ;
    PORT
      LAYER M4 ;
        RECT 729.8500 1239.4800 729.9500 1240.0000 ;
    END
  END out[52]
  PIN out[51]
    DIRECTION OUTPUT ;
    USE SIGNAL ;
    PORT
      LAYER M4 ;
        RECT 733.8500 1239.4800 733.9500 1240.0000 ;
    END
  END out[51]
  PIN out[50]
    DIRECTION OUTPUT ;
    USE SIGNAL ;
    PORT
      LAYER M4 ;
        RECT 737.8500 1239.4800 737.9500 1240.0000 ;
    END
  END out[50]
  PIN out[49]
    DIRECTION OUTPUT ;
    USE SIGNAL ;
    PORT
      LAYER M4 ;
        RECT 741.8500 1239.4800 741.9500 1240.0000 ;
    END
  END out[49]
  PIN out[48]
    DIRECTION OUTPUT ;
    USE SIGNAL ;
    PORT
      LAYER M4 ;
        RECT 745.8500 1239.4800 745.9500 1240.0000 ;
    END
  END out[48]
  PIN out[47]
    DIRECTION OUTPUT ;
    USE SIGNAL ;
    PORT
      LAYER M4 ;
        RECT 749.8500 1239.4800 749.9500 1240.0000 ;
    END
  END out[47]
  PIN out[46]
    DIRECTION OUTPUT ;
    USE SIGNAL ;
    PORT
      LAYER M4 ;
        RECT 753.8500 1239.4800 753.9500 1240.0000 ;
    END
  END out[46]
  PIN out[45]
    DIRECTION OUTPUT ;
    USE SIGNAL ;
    PORT
      LAYER M4 ;
        RECT 757.8500 1239.4800 757.9500 1240.0000 ;
    END
  END out[45]
  PIN out[44]
    DIRECTION OUTPUT ;
    USE SIGNAL ;
    PORT
      LAYER M4 ;
        RECT 761.8500 1239.4800 761.9500 1240.0000 ;
    END
  END out[44]
  PIN out[43]
    DIRECTION OUTPUT ;
    USE SIGNAL ;
    PORT
      LAYER M4 ;
        RECT 765.8500 1239.4800 765.9500 1240.0000 ;
    END
  END out[43]
  PIN out[42]
    DIRECTION OUTPUT ;
    USE SIGNAL ;
    PORT
      LAYER M4 ;
        RECT 769.8500 1239.4800 769.9500 1240.0000 ;
    END
  END out[42]
  PIN out[41]
    DIRECTION OUTPUT ;
    USE SIGNAL ;
    PORT
      LAYER M4 ;
        RECT 773.8500 1239.4800 773.9500 1240.0000 ;
    END
  END out[41]
  PIN out[40]
    DIRECTION OUTPUT ;
    USE SIGNAL ;
    PORT
      LAYER M4 ;
        RECT 777.8500 1239.4800 777.9500 1240.0000 ;
    END
  END out[40]
  PIN out[39]
    DIRECTION OUTPUT ;
    USE SIGNAL ;
    PORT
      LAYER M4 ;
        RECT 781.8500 1239.4800 781.9500 1240.0000 ;
    END
  END out[39]
  PIN out[38]
    DIRECTION OUTPUT ;
    USE SIGNAL ;
    PORT
      LAYER M4 ;
        RECT 785.8500 1239.4800 785.9500 1240.0000 ;
    END
  END out[38]
  PIN out[37]
    DIRECTION OUTPUT ;
    USE SIGNAL ;
    PORT
      LAYER M4 ;
        RECT 789.8500 1239.4800 789.9500 1240.0000 ;
    END
  END out[37]
  PIN out[36]
    DIRECTION OUTPUT ;
    USE SIGNAL ;
    PORT
      LAYER M4 ;
        RECT 793.8500 1239.4800 793.9500 1240.0000 ;
    END
  END out[36]
  PIN out[35]
    DIRECTION OUTPUT ;
    USE SIGNAL ;
    PORT
      LAYER M4 ;
        RECT 797.8500 1239.4800 797.9500 1240.0000 ;
    END
  END out[35]
  PIN out[34]
    DIRECTION OUTPUT ;
    USE SIGNAL ;
    PORT
      LAYER M4 ;
        RECT 801.8500 1239.4800 801.9500 1240.0000 ;
    END
  END out[34]
  PIN out[33]
    DIRECTION OUTPUT ;
    USE SIGNAL ;
    PORT
      LAYER M4 ;
        RECT 805.8500 1239.4800 805.9500 1240.0000 ;
    END
  END out[33]
  PIN out[32]
    DIRECTION OUTPUT ;
    USE SIGNAL ;
    PORT
      LAYER M4 ;
        RECT 809.8500 1239.4800 809.9500 1240.0000 ;
    END
  END out[32]
  PIN out[31]
    DIRECTION OUTPUT ;
    USE SIGNAL ;
    PORT
      LAYER M4 ;
        RECT 813.8500 1239.4800 813.9500 1240.0000 ;
    END
  END out[31]
  PIN out[30]
    DIRECTION OUTPUT ;
    USE SIGNAL ;
    PORT
      LAYER M4 ;
        RECT 817.8500 1239.4800 817.9500 1240.0000 ;
    END
  END out[30]
  PIN out[29]
    DIRECTION OUTPUT ;
    USE SIGNAL ;
    PORT
      LAYER M4 ;
        RECT 821.8500 1239.4800 821.9500 1240.0000 ;
    END
  END out[29]
  PIN out[28]
    DIRECTION OUTPUT ;
    USE SIGNAL ;
    PORT
      LAYER M4 ;
        RECT 825.8500 1239.4800 825.9500 1240.0000 ;
    END
  END out[28]
  PIN out[27]
    DIRECTION OUTPUT ;
    USE SIGNAL ;
    PORT
      LAYER M4 ;
        RECT 829.8500 1239.4800 829.9500 1240.0000 ;
    END
  END out[27]
  PIN out[26]
    DIRECTION OUTPUT ;
    USE SIGNAL ;
    PORT
      LAYER M4 ;
        RECT 833.8500 1239.4800 833.9500 1240.0000 ;
    END
  END out[26]
  PIN out[25]
    DIRECTION OUTPUT ;
    USE SIGNAL ;
    PORT
      LAYER M4 ;
        RECT 837.8500 1239.4800 837.9500 1240.0000 ;
    END
  END out[25]
  PIN out[24]
    DIRECTION OUTPUT ;
    USE SIGNAL ;
    PORT
      LAYER M4 ;
        RECT 841.8500 1239.4800 841.9500 1240.0000 ;
    END
  END out[24]
  PIN out[23]
    DIRECTION OUTPUT ;
    USE SIGNAL ;
    PORT
      LAYER M4 ;
        RECT 845.8500 1239.4800 845.9500 1240.0000 ;
    END
  END out[23]
  PIN out[22]
    DIRECTION OUTPUT ;
    USE SIGNAL ;
    PORT
      LAYER M4 ;
        RECT 849.8500 1239.4800 849.9500 1240.0000 ;
    END
  END out[22]
  PIN out[21]
    DIRECTION OUTPUT ;
    USE SIGNAL ;
    PORT
      LAYER M4 ;
        RECT 853.8500 1239.4800 853.9500 1240.0000 ;
    END
  END out[21]
  PIN out[20]
    DIRECTION OUTPUT ;
    USE SIGNAL ;
    PORT
      LAYER M4 ;
        RECT 857.8500 1239.4800 857.9500 1240.0000 ;
    END
  END out[20]
  PIN out[19]
    DIRECTION OUTPUT ;
    USE SIGNAL ;
    PORT
      LAYER M4 ;
        RECT 861.8500 1239.4800 861.9500 1240.0000 ;
    END
  END out[19]
  PIN out[18]
    DIRECTION OUTPUT ;
    USE SIGNAL ;
    PORT
      LAYER M4 ;
        RECT 865.8500 1239.4800 865.9500 1240.0000 ;
    END
  END out[18]
  PIN out[17]
    DIRECTION OUTPUT ;
    USE SIGNAL ;
    PORT
      LAYER M4 ;
        RECT 869.8500 1239.4800 869.9500 1240.0000 ;
    END
  END out[17]
  PIN out[16]
    DIRECTION OUTPUT ;
    USE SIGNAL ;
    PORT
      LAYER M4 ;
        RECT 873.8500 1239.4800 873.9500 1240.0000 ;
    END
  END out[16]
  PIN out[15]
    DIRECTION OUTPUT ;
    USE SIGNAL ;
    PORT
      LAYER M4 ;
        RECT 877.8500 1239.4800 877.9500 1240.0000 ;
    END
  END out[15]
  PIN out[14]
    DIRECTION OUTPUT ;
    USE SIGNAL ;
    PORT
      LAYER M4 ;
        RECT 881.8500 1239.4800 881.9500 1240.0000 ;
    END
  END out[14]
  PIN out[13]
    DIRECTION OUTPUT ;
    USE SIGNAL ;
    PORT
      LAYER M4 ;
        RECT 885.8500 1239.4800 885.9500 1240.0000 ;
    END
  END out[13]
  PIN out[12]
    DIRECTION OUTPUT ;
    USE SIGNAL ;
    PORT
      LAYER M4 ;
        RECT 889.8500 1239.4800 889.9500 1240.0000 ;
    END
  END out[12]
  PIN out[11]
    DIRECTION OUTPUT ;
    USE SIGNAL ;
    PORT
      LAYER M4 ;
        RECT 893.8500 1239.4800 893.9500 1240.0000 ;
    END
  END out[11]
  PIN out[10]
    DIRECTION OUTPUT ;
    USE SIGNAL ;
    PORT
      LAYER M4 ;
        RECT 897.8500 1239.4800 897.9500 1240.0000 ;
    END
  END out[10]
  PIN out[9]
    DIRECTION OUTPUT ;
    USE SIGNAL ;
    PORT
      LAYER M4 ;
        RECT 901.8500 1239.4800 901.9500 1240.0000 ;
    END
  END out[9]
  PIN out[8]
    DIRECTION OUTPUT ;
    USE SIGNAL ;
    PORT
      LAYER M4 ;
        RECT 905.8500 1239.4800 905.9500 1240.0000 ;
    END
  END out[8]
  PIN out[7]
    DIRECTION OUTPUT ;
    USE SIGNAL ;
    PORT
      LAYER M4 ;
        RECT 909.8500 1239.4800 909.9500 1240.0000 ;
    END
  END out[7]
  PIN out[6]
    DIRECTION OUTPUT ;
    USE SIGNAL ;
    PORT
      LAYER M4 ;
        RECT 913.8500 1239.4800 913.9500 1240.0000 ;
    END
  END out[6]
  PIN out[5]
    DIRECTION OUTPUT ;
    USE SIGNAL ;
    PORT
      LAYER M4 ;
        RECT 917.8500 1239.4800 917.9500 1240.0000 ;
    END
  END out[5]
  PIN out[4]
    DIRECTION OUTPUT ;
    USE SIGNAL ;
    PORT
      LAYER M4 ;
        RECT 921.8500 1239.4800 921.9500 1240.0000 ;
    END
  END out[4]
  PIN out[3]
    DIRECTION OUTPUT ;
    USE SIGNAL ;
    PORT
      LAYER M4 ;
        RECT 925.8500 1239.4800 925.9500 1240.0000 ;
    END
  END out[3]
  PIN out[2]
    DIRECTION OUTPUT ;
    USE SIGNAL ;
    PORT
      LAYER M4 ;
        RECT 929.8500 1239.4800 929.9500 1240.0000 ;
    END
  END out[2]
  PIN out[1]
    DIRECTION OUTPUT ;
    USE SIGNAL ;
    PORT
      LAYER M4 ;
        RECT 933.8500 1239.4800 933.9500 1240.0000 ;
    END
  END out[1]
  PIN out[0]
    DIRECTION OUTPUT ;
    USE SIGNAL ;
    PORT
      LAYER M4 ;
        RECT 937.8500 1239.4800 937.9500 1240.0000 ;
    END
  END out[0]
  PIN inst[19]
    DIRECTION INPUT ;
    USE SIGNAL ;
    PORT
      LAYER M3 ;
        RECT 1239.4800 610.1500 1240.0000 610.2500 ;
    END
  END inst[19]
  PIN inst[18]
    DIRECTION INPUT ;
    USE SIGNAL ;
    PORT
      LAYER M3 ;
        RECT 1239.4800 606.1500 1240.0000 606.2500 ;
    END
  END inst[18]
  PIN inst[17]
    DIRECTION INPUT ;
    USE SIGNAL ;
    PORT
      LAYER M3 ;
        RECT 1239.4800 602.1500 1240.0000 602.2500 ;
    END
  END inst[17]
  PIN inst[16]
    DIRECTION INPUT ;
    USE SIGNAL ;
    PORT
      LAYER M3 ;
        RECT 1239.4800 598.1500 1240.0000 598.2500 ;
    END
  END inst[16]
  PIN inst[15]
    DIRECTION INPUT ;
    USE SIGNAL ;
    PORT
      LAYER M3 ;
        RECT 1239.4800 594.1500 1240.0000 594.2500 ;
    END
  END inst[15]
  PIN inst[14]
    DIRECTION INPUT ;
    USE SIGNAL ;
    PORT
      LAYER M3 ;
        RECT 1239.4800 590.1500 1240.0000 590.2500 ;
    END
  END inst[14]
  PIN inst[13]
    DIRECTION INPUT ;
    USE SIGNAL ;
    PORT
      LAYER M3 ;
        RECT 1239.4800 586.1500 1240.0000 586.2500 ;
    END
  END inst[13]
  PIN inst[12]
    DIRECTION INPUT ;
    USE SIGNAL ;
    PORT
      LAYER M3 ;
        RECT 1239.4800 582.1500 1240.0000 582.2500 ;
    END
  END inst[12]
  PIN inst[11]
    DIRECTION INPUT ;
    USE SIGNAL ;
    PORT
      LAYER M3 ;
        RECT 1239.4800 578.1500 1240.0000 578.2500 ;
    END
  END inst[11]
  PIN inst[10]
    DIRECTION INPUT ;
    USE SIGNAL ;
    PORT
      LAYER M3 ;
        RECT 1239.4800 574.1500 1240.0000 574.2500 ;
    END
  END inst[10]
  PIN inst[9]
    DIRECTION INPUT ;
    USE SIGNAL ;
    PORT
      LAYER M3 ;
        RECT 1239.4800 570.1500 1240.0000 570.2500 ;
    END
  END inst[9]
  PIN inst[8]
    DIRECTION INPUT ;
    USE SIGNAL ;
    PORT
      LAYER M3 ;
        RECT 1239.4800 566.1500 1240.0000 566.2500 ;
    END
  END inst[8]
  PIN inst[7]
    DIRECTION INPUT ;
    USE SIGNAL ;
    PORT
      LAYER M3 ;
        RECT 1239.4800 562.1500 1240.0000 562.2500 ;
    END
  END inst[7]
  PIN inst[6]
    DIRECTION INPUT ;
    USE SIGNAL ;
    PORT
      LAYER M3 ;
        RECT 1239.4800 558.1500 1240.0000 558.2500 ;
    END
  END inst[6]
  PIN inst[5]
    DIRECTION INPUT ;
    USE SIGNAL ;
    PORT
      LAYER M3 ;
        RECT 1239.4800 554.1500 1240.0000 554.2500 ;
    END
  END inst[5]
  PIN inst[4]
    DIRECTION INPUT ;
    USE SIGNAL ;
    PORT
      LAYER M3 ;
        RECT 1239.4800 550.1500 1240.0000 550.2500 ;
    END
  END inst[4]
  PIN inst[3]
    DIRECTION INPUT ;
    USE SIGNAL ;
    PORT
      LAYER M3 ;
        RECT 1239.4800 546.1500 1240.0000 546.2500 ;
    END
  END inst[3]
  PIN inst[2]
    DIRECTION INPUT ;
    USE SIGNAL ;
    PORT
      LAYER M3 ;
        RECT 1239.4800 542.1500 1240.0000 542.2500 ;
    END
  END inst[2]
  PIN inst[1]
    DIRECTION INPUT ;
    USE SIGNAL ;
    PORT
      LAYER M3 ;
        RECT 1239.4800 538.1500 1240.0000 538.2500 ;
    END
  END inst[1]
  PIN inst[0]
    DIRECTION INPUT ;
    USE SIGNAL ;
    PORT
      LAYER M3 ;
        RECT 1239.4800 534.1500 1240.0000 534.2500 ;
    END
  END inst[0]
  PIN reset
    DIRECTION INPUT ;
    USE SIGNAL ;
    PORT
      LAYER M3 ;
        RECT 0.0000 617.7500 0.5200 617.8500 ;
    END
  END reset
  PIN ext_fifo_wr
    DIRECTION OUTPUT ;
    USE SIGNAL ;
    PORT
      LAYER M3 ;
        RECT 0.0000 621.7500 0.5200 621.8500 ;
    END
  END ext_fifo_wr
  PIN ext_fifo_in[23]
    DIRECTION OUTPUT ;
    USE SIGNAL ;
    PORT
      LAYER M3 ;
        RECT 1239.4800 706.1500 1240.0000 706.2500 ;
    END
  END ext_fifo_in[23]
  PIN ext_fifo_in[22]
    DIRECTION OUTPUT ;
    USE SIGNAL ;
    PORT
      LAYER M3 ;
        RECT 1239.4800 702.1500 1240.0000 702.2500 ;
    END
  END ext_fifo_in[22]
  PIN ext_fifo_in[21]
    DIRECTION OUTPUT ;
    USE SIGNAL ;
    PORT
      LAYER M3 ;
        RECT 1239.4800 698.1500 1240.0000 698.2500 ;
    END
  END ext_fifo_in[21]
  PIN ext_fifo_in[20]
    DIRECTION OUTPUT ;
    USE SIGNAL ;
    PORT
      LAYER M3 ;
        RECT 1239.4800 694.1500 1240.0000 694.2500 ;
    END
  END ext_fifo_in[20]
  PIN ext_fifo_in[19]
    DIRECTION OUTPUT ;
    USE SIGNAL ;
    PORT
      LAYER M3 ;
        RECT 1239.4800 690.1500 1240.0000 690.2500 ;
    END
  END ext_fifo_in[19]
  PIN ext_fifo_in[18]
    DIRECTION OUTPUT ;
    USE SIGNAL ;
    PORT
      LAYER M3 ;
        RECT 1239.4800 686.1500 1240.0000 686.2500 ;
    END
  END ext_fifo_in[18]
  PIN ext_fifo_in[17]
    DIRECTION OUTPUT ;
    USE SIGNAL ;
    PORT
      LAYER M3 ;
        RECT 1239.4800 682.1500 1240.0000 682.2500 ;
    END
  END ext_fifo_in[17]
  PIN ext_fifo_in[16]
    DIRECTION OUTPUT ;
    USE SIGNAL ;
    PORT
      LAYER M3 ;
        RECT 1239.4800 678.1500 1240.0000 678.2500 ;
    END
  END ext_fifo_in[16]
  PIN ext_fifo_in[15]
    DIRECTION OUTPUT ;
    USE SIGNAL ;
    PORT
      LAYER M3 ;
        RECT 1239.4800 674.1500 1240.0000 674.2500 ;
    END
  END ext_fifo_in[15]
  PIN ext_fifo_in[14]
    DIRECTION OUTPUT ;
    USE SIGNAL ;
    PORT
      LAYER M3 ;
        RECT 1239.4800 670.1500 1240.0000 670.2500 ;
    END
  END ext_fifo_in[14]
  PIN ext_fifo_in[13]
    DIRECTION OUTPUT ;
    USE SIGNAL ;
    PORT
      LAYER M3 ;
        RECT 1239.4800 666.1500 1240.0000 666.2500 ;
    END
  END ext_fifo_in[13]
  PIN ext_fifo_in[12]
    DIRECTION OUTPUT ;
    USE SIGNAL ;
    PORT
      LAYER M3 ;
        RECT 1239.4800 662.1500 1240.0000 662.2500 ;
    END
  END ext_fifo_in[12]
  PIN ext_fifo_in[11]
    DIRECTION OUTPUT ;
    USE SIGNAL ;
    PORT
      LAYER M3 ;
        RECT 1239.4800 658.1500 1240.0000 658.2500 ;
    END
  END ext_fifo_in[11]
  PIN ext_fifo_in[10]
    DIRECTION OUTPUT ;
    USE SIGNAL ;
    PORT
      LAYER M3 ;
        RECT 1239.4800 654.1500 1240.0000 654.2500 ;
    END
  END ext_fifo_in[10]
  PIN ext_fifo_in[9]
    DIRECTION OUTPUT ;
    USE SIGNAL ;
    PORT
      LAYER M3 ;
        RECT 1239.4800 650.1500 1240.0000 650.2500 ;
    END
  END ext_fifo_in[9]
  PIN ext_fifo_in[8]
    DIRECTION OUTPUT ;
    USE SIGNAL ;
    PORT
      LAYER M3 ;
        RECT 1239.4800 646.1500 1240.0000 646.2500 ;
    END
  END ext_fifo_in[8]
  PIN ext_fifo_in[7]
    DIRECTION OUTPUT ;
    USE SIGNAL ;
    PORT
      LAYER M3 ;
        RECT 1239.4800 642.1500 1240.0000 642.2500 ;
    END
  END ext_fifo_in[7]
  PIN ext_fifo_in[6]
    DIRECTION OUTPUT ;
    USE SIGNAL ;
    PORT
      LAYER M3 ;
        RECT 1239.4800 638.1500 1240.0000 638.2500 ;
    END
  END ext_fifo_in[6]
  PIN ext_fifo_in[5]
    DIRECTION OUTPUT ;
    USE SIGNAL ;
    PORT
      LAYER M3 ;
        RECT 1239.4800 634.1500 1240.0000 634.2500 ;
    END
  END ext_fifo_in[5]
  PIN ext_fifo_in[4]
    DIRECTION OUTPUT ;
    USE SIGNAL ;
    PORT
      LAYER M3 ;
        RECT 1239.4800 630.1500 1240.0000 630.2500 ;
    END
  END ext_fifo_in[4]
  PIN ext_fifo_in[3]
    DIRECTION OUTPUT ;
    USE SIGNAL ;
    PORT
      LAYER M3 ;
        RECT 1239.4800 626.1500 1240.0000 626.2500 ;
    END
  END ext_fifo_in[3]
  PIN ext_fifo_in[2]
    DIRECTION OUTPUT ;
    USE SIGNAL ;
    PORT
      LAYER M3 ;
        RECT 1239.4800 622.1500 1240.0000 622.2500 ;
    END
  END ext_fifo_in[2]
  PIN ext_fifo_in[1]
    DIRECTION OUTPUT ;
    USE SIGNAL ;
    PORT
      LAYER M3 ;
        RECT 1239.4800 618.1500 1240.0000 618.2500 ;
    END
  END ext_fifo_in[1]
  PIN ext_fifo_in[0]
    DIRECTION OUTPUT ;
    USE SIGNAL ;
    PORT
      LAYER M3 ;
        RECT 1239.4800 614.1500 1240.0000 614.2500 ;
    END
  END ext_fifo_in[0]
  PIN ext_fifo_rd
    DIRECTION OUTPUT ;
    USE SIGNAL ;
    PORT
      LAYER M3 ;
        RECT 0.0000 625.7500 0.5200 625.8500 ;
    END
  END ext_fifo_rd
  PIN VSS
    DIRECTION INOUT ;
    USE GROUND ;

# P/G power stripe data as pin
    PORT
      LAYER M4 ;
        RECT 97.5000 128.6600 98.0000 129.6600 ;
        RECT 97.5000 177.9900 98.0000 178.9900 ;
        RECT 97.5000 227.3200 98.0000 228.3200 ;
        RECT 97.5000 276.6500 98.0000 277.6500 ;
        RECT 302.1650 171.2500 305.1650 171.7500 ;
        RECT 377.0000 128.6600 377.5000 129.6600 ;
        RECT 447.5000 128.6600 448.0000 129.6600 ;
        RECT 377.0000 171.2500 377.5000 171.7500 ;
        RECT 377.0000 177.9900 377.5000 178.9900 ;
        RECT 377.0000 227.3200 377.5000 228.3200 ;
        RECT 447.5000 177.9900 448.0000 178.9900 ;
        RECT 447.5000 227.3200 448.0000 228.3200 ;
        RECT 377.0000 276.6500 377.5000 277.6500 ;
        RECT 447.5000 276.6500 448.0000 277.6500 ;
        RECT 97.5000 325.9800 98.0000 326.9800 ;
        RECT 97.5000 375.3100 98.0000 376.3100 ;
        RECT 97.5000 473.9700 98.0000 474.9700 ;
        RECT 123.0000 473.9700 126.0000 474.9700 ;
        RECT 97.5000 523.3000 98.0000 524.3000 ;
        RECT 123.0000 523.3000 126.0000 524.3000 ;
        RECT 97.5000 572.6300 98.0000 573.6300 ;
        RECT 123.0000 572.6300 126.0000 573.6300 ;
        RECT 249.8000 473.9700 252.8000 474.9700 ;
        RECT 249.8000 523.3000 252.8000 524.3000 ;
        RECT 249.8000 572.6300 252.8000 573.6300 ;
        RECT 377.0000 325.9800 377.5000 326.9800 ;
        RECT 377.0000 375.3100 377.5000 376.3100 ;
        RECT 447.5000 325.9800 448.0000 326.9800 ;
        RECT 447.5000 375.3100 448.0000 376.3100 ;
        RECT 376.6000 473.9700 379.6000 474.9700 ;
        RECT 503.4000 473.9700 506.4000 474.9700 ;
        RECT 376.6000 523.3000 379.6000 524.3000 ;
        RECT 503.4000 523.3000 506.4000 524.3000 ;
        RECT 376.6000 572.6300 379.6000 573.6300 ;
        RECT 503.4000 572.6300 506.4000 573.6300 ;
        RECT 727.0000 128.6600 727.5000 129.6600 ;
        RECT 652.1650 171.2500 655.1650 171.7500 ;
        RECT 727.0000 171.2500 727.5000 171.7500 ;
        RECT 727.0000 177.9900 727.5000 178.9900 ;
        RECT 727.0000 227.3200 727.5000 228.3200 ;
        RECT 727.0000 276.6500 727.5000 277.6500 ;
        RECT 727.0000 325.9800 727.5000 326.9800 ;
        RECT 727.0000 375.3100 727.5000 376.3100 ;
        RECT 630.2000 473.9700 633.2000 474.9700 ;
        RECT 630.2000 523.3000 633.2000 524.3000 ;
        RECT 757.0000 473.9700 760.0000 474.9700 ;
        RECT 772.0000 473.9700 772.5000 474.9700 ;
        RECT 772.0000 523.3000 772.5000 524.3000 ;
        RECT 757.0000 523.3000 760.0000 524.3000 ;
        RECT 630.2000 572.6300 633.2000 573.6300 ;
        RECT 772.0000 572.6300 772.5000 573.6300 ;
        RECT 757.0000 572.6300 760.0000 573.6300 ;
        RECT 97.5000 621.9600 98.0000 622.9600 ;
        RECT 123.0000 621.9600 126.0000 622.9600 ;
        RECT 97.5000 671.2900 98.0000 672.2900 ;
        RECT 123.0000 671.2900 126.0000 672.2900 ;
        RECT 97.5000 720.6200 98.0000 721.6200 ;
        RECT 123.0000 720.6200 126.0000 721.6200 ;
        RECT 97.5000 769.9500 98.0000 770.9500 ;
        RECT 123.0000 769.9500 126.0000 770.9500 ;
        RECT 249.8000 621.9600 252.8000 622.9600 ;
        RECT 249.8000 671.2900 252.8000 672.2900 ;
        RECT 249.8000 720.6200 252.8000 721.6200 ;
        RECT 249.8000 769.9500 252.8000 770.9500 ;
        RECT 97.5000 819.2800 98.0000 820.2800 ;
        RECT 123.0000 819.2800 126.0000 820.2800 ;
        RECT 97.5000 868.6100 98.0000 869.6100 ;
        RECT 123.0000 868.6100 126.0000 869.6100 ;
        RECT 97.5000 917.9400 98.0000 918.9400 ;
        RECT 123.0000 917.9400 126.0000 918.9400 ;
        RECT 249.8000 819.2800 252.8000 820.2800 ;
        RECT 249.8000 868.6100 252.8000 869.6100 ;
        RECT 249.8000 917.9400 252.8000 918.9400 ;
        RECT 503.4000 671.2900 506.4000 672.2900 ;
        RECT 376.6000 671.2900 379.6000 672.2900 ;
        RECT 503.4000 621.9600 506.4000 622.9600 ;
        RECT 376.6000 621.9600 379.6000 622.9600 ;
        RECT 376.6000 720.6200 379.6000 721.6200 ;
        RECT 503.4000 720.6200 506.4000 721.6200 ;
        RECT 376.6000 769.9500 379.6000 770.9500 ;
        RECT 503.4000 769.9500 506.4000 770.9500 ;
        RECT 376.6000 819.2800 379.6000 820.2800 ;
        RECT 503.4000 819.2800 506.4000 820.2800 ;
        RECT 376.6000 868.6100 379.6000 869.6100 ;
        RECT 503.4000 868.6100 506.4000 869.6100 ;
        RECT 376.6000 917.9400 379.6000 918.9400 ;
        RECT 503.4000 917.9400 506.4000 918.9400 ;
        RECT 97.5000 967.2700 98.0000 968.2700 ;
        RECT 123.0000 967.2700 126.0000 968.2700 ;
        RECT 97.5000 1016.6000 98.0000 1017.6000 ;
        RECT 123.0000 1016.6000 126.0000 1017.6000 ;
        RECT 97.5000 1065.9300 98.0000 1066.9300 ;
        RECT 123.0000 1065.9300 126.0000 1066.9300 ;
        RECT 249.8000 967.2700 252.8000 968.2700 ;
        RECT 249.8000 1016.6000 252.8000 1017.6000 ;
        RECT 249.8000 1065.9300 252.8000 1066.9300 ;
        RECT 97.5000 1115.2600 98.0000 1116.2600 ;
        RECT 250.8000 1107.0000 251.8000 1110.0000 ;
        RECT 376.6000 967.2700 379.6000 968.2700 ;
        RECT 503.4000 967.2700 506.4000 968.2700 ;
        RECT 376.6000 1016.6000 379.6000 1017.6000 ;
        RECT 503.4000 1016.6000 506.4000 1017.6000 ;
        RECT 376.6000 1065.9300 379.6000 1066.9300 ;
        RECT 503.4000 1065.9300 506.4000 1066.9300 ;
        RECT 630.2000 621.9600 633.2000 622.9600 ;
        RECT 630.2000 671.2900 633.2000 672.2900 ;
        RECT 772.0000 621.9600 772.5000 622.9600 ;
        RECT 757.0000 621.9600 760.0000 622.9600 ;
        RECT 757.0000 671.2900 760.0000 672.2900 ;
        RECT 772.0000 671.2900 772.5000 672.2900 ;
        RECT 630.2000 720.6200 633.2000 721.6200 ;
        RECT 630.2000 769.9500 633.2000 770.9500 ;
        RECT 757.0000 720.6200 760.0000 721.6200 ;
        RECT 772.0000 720.6200 772.5000 721.6200 ;
        RECT 757.0000 769.9500 760.0000 770.9500 ;
        RECT 772.0000 769.9500 772.5000 770.9500 ;
        RECT 630.2000 819.2800 633.2000 820.2800 ;
        RECT 772.0000 819.2800 772.5000 820.2800 ;
        RECT 757.0000 819.2800 760.0000 820.2800 ;
        RECT 630.2000 868.6100 633.2000 869.6100 ;
        RECT 630.2000 917.9400 633.2000 918.9400 ;
        RECT 757.0000 868.6100 760.0000 869.6100 ;
        RECT 772.0000 868.6100 772.5000 869.6100 ;
        RECT 757.0000 917.9400 760.0000 918.9400 ;
        RECT 772.0000 917.9400 772.5000 918.9400 ;
        RECT 630.2000 967.2700 633.2000 968.2700 ;
        RECT 772.0000 967.2700 772.5000 968.2700 ;
        RECT 757.0000 967.2700 760.0000 968.2700 ;
        RECT 630.2000 1016.6000 633.2000 1017.6000 ;
        RECT 630.2000 1065.9300 633.2000 1066.9300 ;
        RECT 772.0000 1016.6000 772.5000 1017.6000 ;
        RECT 757.0000 1016.6000 760.0000 1017.6000 ;
        RECT 772.0000 1065.9300 772.5000 1066.9300 ;
        RECT 757.0000 1065.9300 760.0000 1066.9300 ;
        RECT 772.0000 1115.2600 772.5000 1116.2600 ;
    END
# end of P/G power stripe data as pin


# P/G pin shape extracted from block 'sram_w16'
    PORT
      LAYER M4 ;
        RECT 654.8350 170.0000 655.1650 173.0000 ;
        RECT 654.8350 194.4400 655.1650 197.4400 ;
        RECT 654.8350 218.8800 655.1650 221.8800 ;
        RECT 654.8350 243.3200 655.1650 246.3200 ;
        RECT 654.8350 267.7600 655.1650 270.7600 ;
        RECT 654.8350 292.2000 655.1650 295.2000 ;
        RECT 520.0000 292.2000 655.0000 295.2000 ;
        RECT 520.0000 267.7600 655.0000 270.7600 ;
        RECT 520.0000 243.3200 655.0000 246.3200 ;
        RECT 520.0000 218.8800 655.0000 221.8800 ;
        RECT 520.0000 194.4400 655.0000 197.4400 ;
        RECT 520.0000 170.0000 655.0000 173.0000 ;
    END
# end of P/G pin shape extracted from block 'sram_w16'


# P/G pin shape extracted from block 'sram_w16'
    PORT
      LAYER M4 ;
        RECT 304.8350 170.0000 305.1650 173.0000 ;
        RECT 304.8350 194.4400 305.1650 197.4400 ;
        RECT 304.8350 218.8800 305.1650 221.8800 ;
        RECT 304.8350 243.3200 305.1650 246.3200 ;
        RECT 304.8350 267.7600 305.1650 270.7600 ;
        RECT 304.8350 292.2000 305.1650 295.2000 ;
        RECT 170.0000 292.2000 305.0000 295.2000 ;
        RECT 170.0000 267.7600 305.0000 270.7600 ;
        RECT 170.0000 243.3200 305.0000 246.3200 ;
        RECT 170.0000 218.8800 305.0000 221.8800 ;
        RECT 170.0000 194.4400 305.0000 197.4400 ;
        RECT 170.0000 170.0000 305.0000 173.0000 ;
    END
# end of P/G pin shape extracted from block 'sram_w16'


# P/G pin shape extracted from block 'sram_160b_w16'
    PORT
      LAYER M4 ;
        RECT 123.0000 460.0000 126.0000 1110.0000 ;
        RECT 249.8000 460.0000 252.8000 1110.0000 ;
        RECT 376.6000 460.0000 379.6000 1110.0000 ;
        RECT 503.4000 460.0000 506.4000 1110.0000 ;
        RECT 630.2000 460.0000 633.2000 1110.0000 ;
        RECT 757.0000 460.0000 760.0000 1110.0000 ;
    END
# end of P/G pin shape extracted from block 'sram_160b_w16'

  END VSS
  PIN VDD
    DIRECTION INOUT ;
    USE POWER ;

# P/G power stripe data as pin
    PORT
      LAYER M4 ;
        RECT 617.2000 468.9700 620.2000 469.9700 ;
        RECT 617.2000 518.3000 620.2000 519.3000 ;
        RECT 617.2000 567.6300 620.2000 568.6300 ;
        RECT 617.2000 616.9600 620.2000 617.9600 ;
        RECT 98.5000 123.6600 99.0000 124.6600 ;
        RECT 98.5000 172.9900 99.0000 173.9900 ;
        RECT 98.5000 222.3200 99.0000 223.3200 ;
        RECT 98.5000 271.6500 99.0000 272.6500 ;
        RECT 98.5000 282.0100 99.0000 282.5100 ;
        RECT 169.8350 282.0100 172.8350 282.5100 ;
        RECT 376.0000 123.6600 376.5000 124.6600 ;
        RECT 448.5000 123.6600 449.0000 124.6600 ;
        RECT 376.0000 172.9900 376.5000 173.9900 ;
        RECT 376.0000 222.3200 376.5000 223.3200 ;
        RECT 448.5000 172.9900 449.0000 173.9900 ;
        RECT 448.5000 222.3200 449.0000 223.3200 ;
        RECT 376.0000 271.6500 376.5000 272.6500 ;
        RECT 448.5000 271.6500 449.0000 272.6500 ;
        RECT 448.5000 282.0100 449.0000 282.5100 ;
        RECT 519.8350 282.0100 522.8350 282.5100 ;
        RECT 98.5000 320.9800 99.0000 321.9800 ;
        RECT 98.5000 370.3100 99.0000 371.3100 ;
        RECT 98.5000 468.9700 99.0000 469.9700 ;
        RECT 110.0000 468.9700 113.0000 469.9700 ;
        RECT 98.5000 518.3000 99.0000 519.3000 ;
        RECT 110.0000 518.3000 113.0000 519.3000 ;
        RECT 98.5000 567.6300 99.0000 568.6300 ;
        RECT 110.0000 567.6300 113.0000 568.6300 ;
        RECT 98.5000 616.9600 99.0000 617.9600 ;
        RECT 110.0000 616.9600 113.0000 617.9600 ;
        RECT 236.8000 468.9700 239.8000 469.9700 ;
        RECT 236.8000 518.3000 239.8000 519.3000 ;
        RECT 236.8000 567.6300 239.8000 568.6300 ;
        RECT 236.8000 616.9600 239.8000 617.9600 ;
        RECT 376.0000 320.9800 376.5000 321.9800 ;
        RECT 376.0000 370.3100 376.5000 371.3100 ;
        RECT 448.5000 320.9800 449.0000 321.9800 ;
        RECT 448.5000 370.3100 449.0000 371.3100 ;
        RECT 363.6000 468.9700 366.6000 469.9700 ;
        RECT 490.4000 468.9700 493.4000 469.9700 ;
        RECT 363.6000 518.3000 366.6000 519.3000 ;
        RECT 490.4000 518.3000 493.4000 519.3000 ;
        RECT 363.6000 567.6300 366.6000 568.6300 ;
        RECT 490.4000 567.6300 493.4000 568.6300 ;
        RECT 363.6000 616.9600 366.6000 617.9600 ;
        RECT 490.4000 616.9600 493.4000 617.9600 ;
        RECT 726.0000 123.6600 726.5000 124.6600 ;
        RECT 726.0000 172.9900 726.5000 173.9900 ;
        RECT 726.0000 222.3200 726.5000 223.3200 ;
        RECT 726.0000 271.6500 726.5000 272.6500 ;
        RECT 726.0000 320.9800 726.5000 321.9800 ;
        RECT 726.0000 370.3100 726.5000 371.3100 ;
        RECT 744.0000 468.9700 747.0000 469.9700 ;
        RECT 771.0000 468.9700 771.5000 469.9700 ;
        RECT 744.0000 518.3000 747.0000 519.3000 ;
        RECT 771.0000 518.3000 771.5000 519.3000 ;
        RECT 744.0000 567.6300 747.0000 568.6300 ;
        RECT 771.0000 567.6300 771.5000 568.6300 ;
        RECT 744.0000 616.9600 747.0000 617.9600 ;
        RECT 771.0000 616.9600 771.5000 617.9600 ;
        RECT 617.2000 666.2900 620.2000 667.2900 ;
        RECT 617.2000 715.6200 620.2000 716.6200 ;
        RECT 617.2000 764.9500 620.2000 765.9500 ;
        RECT 617.2000 814.2800 620.2000 815.2800 ;
        RECT 617.2000 863.6100 620.2000 864.6100 ;
        RECT 617.2000 912.9400 620.2000 913.9400 ;
        RECT 617.2000 962.2700 620.2000 963.2700 ;
        RECT 617.2000 1011.6000 620.2000 1012.6000 ;
        RECT 617.2000 1060.9300 620.2000 1061.9300 ;
        RECT 98.5000 666.2900 99.0000 667.2900 ;
        RECT 110.0000 666.2900 113.0000 667.2900 ;
        RECT 98.5000 715.6200 99.0000 716.6200 ;
        RECT 110.0000 715.6200 113.0000 716.6200 ;
        RECT 98.5000 764.9500 99.0000 765.9500 ;
        RECT 110.0000 764.9500 113.0000 765.9500 ;
        RECT 236.8000 666.2900 239.8000 667.2900 ;
        RECT 236.8000 715.6200 239.8000 716.6200 ;
        RECT 236.8000 764.9500 239.8000 765.9500 ;
        RECT 98.5000 814.2800 99.0000 815.2800 ;
        RECT 110.0000 814.2800 113.0000 815.2800 ;
        RECT 98.5000 863.6100 99.0000 864.6100 ;
        RECT 110.0000 863.6100 113.0000 864.6100 ;
        RECT 98.5000 912.9400 99.0000 913.9400 ;
        RECT 110.0000 912.9400 113.0000 913.9400 ;
        RECT 236.8000 814.2800 239.8000 815.2800 ;
        RECT 236.8000 863.6100 239.8000 864.6100 ;
        RECT 236.8000 912.9400 239.8000 913.9400 ;
        RECT 363.6000 666.2900 366.6000 667.2900 ;
        RECT 490.4000 666.2900 493.4000 667.2900 ;
        RECT 363.6000 715.6200 366.6000 716.6200 ;
        RECT 490.4000 715.6200 493.4000 716.6200 ;
        RECT 363.6000 764.9500 366.6000 765.9500 ;
        RECT 490.4000 764.9500 493.4000 765.9500 ;
        RECT 363.6000 814.2800 366.6000 815.2800 ;
        RECT 490.4000 814.2800 493.4000 815.2800 ;
        RECT 363.6000 863.6100 366.6000 864.6100 ;
        RECT 490.4000 863.6100 493.4000 864.6100 ;
        RECT 363.6000 912.9400 366.6000 913.9400 ;
        RECT 490.4000 912.9400 493.4000 913.9400 ;
        RECT 98.5000 962.2700 99.0000 963.2700 ;
        RECT 110.0000 962.2700 113.0000 963.2700 ;
        RECT 98.5000 1011.6000 99.0000 1012.6000 ;
        RECT 110.0000 1011.6000 113.0000 1012.6000 ;
        RECT 110.0000 1060.9300 113.0000 1061.9300 ;
        RECT 98.5000 1060.9300 99.0000 1061.9300 ;
        RECT 236.8000 962.2700 239.8000 963.2700 ;
        RECT 236.8000 1011.6000 239.8000 1012.6000 ;
        RECT 236.8000 1060.9300 239.8000 1061.9300 ;
        RECT 98.5000 1110.2600 99.0000 1111.2600 ;
        RECT 237.8000 1107.1650 238.8000 1110.1650 ;
        RECT 363.6000 962.2700 366.6000 963.2700 ;
        RECT 490.4000 962.2700 493.4000 963.2700 ;
        RECT 363.6000 1011.6000 366.6000 1012.6000 ;
        RECT 490.4000 1011.6000 493.4000 1012.6000 ;
        RECT 363.6000 1060.9300 366.6000 1061.9300 ;
        RECT 490.4000 1060.9300 493.4000 1061.9300 ;
        RECT 744.0000 666.2900 747.0000 667.2900 ;
        RECT 771.0000 666.2900 771.5000 667.2900 ;
        RECT 744.0000 715.6200 747.0000 716.6200 ;
        RECT 771.0000 715.6200 771.5000 716.6200 ;
        RECT 744.0000 764.9500 747.0000 765.9500 ;
        RECT 771.0000 764.9500 771.5000 765.9500 ;
        RECT 744.0000 814.2800 747.0000 815.2800 ;
        RECT 771.0000 814.2800 771.5000 815.2800 ;
        RECT 744.0000 863.6100 747.0000 864.6100 ;
        RECT 771.0000 863.6100 771.5000 864.6100 ;
        RECT 744.0000 912.9400 747.0000 913.9400 ;
        RECT 771.0000 912.9400 771.5000 913.9400 ;
        RECT 744.0000 962.2700 747.0000 963.2700 ;
        RECT 771.0000 962.2700 771.5000 963.2700 ;
        RECT 744.0000 1011.6000 747.0000 1012.6000 ;
        RECT 771.0000 1011.6000 771.5000 1012.6000 ;
        RECT 744.0000 1060.9300 747.0000 1061.9300 ;
        RECT 771.0000 1060.9300 771.5000 1061.9300 ;
        RECT 771.0000 1110.2600 771.5000 1111.2600 ;
    END
# end of P/G power stripe data as pin


# P/G pin shape extracted from block 'sram_w16'
    PORT
      LAYER M4 ;
        RECT 519.8350 183.0000 520.1650 186.0000 ;
        RECT 519.8350 207.4400 520.1650 210.4400 ;
        RECT 519.8350 231.8800 520.1650 234.8800 ;
        RECT 519.8350 256.3200 520.1650 259.3200 ;
        RECT 519.8350 280.7600 520.1650 283.7600 ;
        RECT 519.8350 305.2000 520.1650 308.2000 ;
        RECT 520.0000 305.2000 655.0000 308.2000 ;
        RECT 520.0000 280.7600 655.0000 283.7600 ;
        RECT 520.0000 256.3200 655.0000 259.3200 ;
        RECT 520.0000 231.8800 655.0000 234.8800 ;
        RECT 520.0000 207.4400 655.0000 210.4400 ;
        RECT 520.0000 183.0000 655.0000 186.0000 ;
    END
# end of P/G pin shape extracted from block 'sram_w16'


# P/G pin shape extracted from block 'sram_w16'
    PORT
      LAYER M4 ;
        RECT 169.8350 183.0000 170.1650 186.0000 ;
        RECT 169.8350 207.4400 170.1650 210.4400 ;
        RECT 169.8350 231.8800 170.1650 234.8800 ;
        RECT 169.8350 256.3200 170.1650 259.3200 ;
        RECT 169.8350 280.7600 170.1650 283.7600 ;
        RECT 169.8350 305.2000 170.1650 308.2000 ;
        RECT 170.0000 305.2000 305.0000 308.2000 ;
        RECT 170.0000 280.7600 305.0000 283.7600 ;
        RECT 170.0000 256.3200 305.0000 259.3200 ;
        RECT 170.0000 231.8800 305.0000 234.8800 ;
        RECT 170.0000 207.4400 305.0000 210.4400 ;
        RECT 170.0000 183.0000 305.0000 186.0000 ;
    END
# end of P/G pin shape extracted from block 'sram_w16'


# P/G pin shape extracted from block 'sram_160b_w16'
    PORT
      LAYER M4 ;
        RECT 744.0000 1109.8350 747.0000 1110.1650 ;
        RECT 617.2000 1109.8350 620.2000 1110.1650 ;
        RECT 490.4000 1109.8350 493.4000 1110.1650 ;
        RECT 363.6000 1109.8350 366.6000 1110.1650 ;
        RECT 236.8000 1109.8350 239.8000 1110.1650 ;
        RECT 110.0000 1109.8350 113.0000 1110.1650 ;
        RECT 110.0000 460.0000 113.0000 1110.0000 ;
        RECT 236.8000 460.0000 239.8000 1110.0000 ;
        RECT 363.6000 460.0000 366.6000 1110.0000 ;
        RECT 490.4000 460.0000 493.4000 1110.0000 ;
        RECT 617.2000 460.0000 620.2000 1110.0000 ;
        RECT 744.0000 460.0000 747.0000 1110.0000 ;
    END
# end of P/G pin shape extracted from block 'sram_160b_w16'

  END VDD
  OBS
    LAYER M1 ;
      RECT 0.0000 0.0000 1240.0000 1240.0000 ;
    LAYER M2 ;
      RECT 0.0000 0.0000 1240.0000 1240.0000 ;
    LAYER M3 ;
      RECT 0.0000 706.3500 1240.0000 1240.0000 ;
      RECT 0.0000 706.0500 1239.3800 706.3500 ;
      RECT 0.0000 702.3500 1240.0000 706.0500 ;
      RECT 0.0000 702.0500 1239.3800 702.3500 ;
      RECT 0.0000 698.3500 1240.0000 702.0500 ;
      RECT 0.0000 698.0500 1239.3800 698.3500 ;
      RECT 0.0000 694.3500 1240.0000 698.0500 ;
      RECT 0.0000 694.0500 1239.3800 694.3500 ;
      RECT 0.0000 690.3500 1240.0000 694.0500 ;
      RECT 0.0000 690.0500 1239.3800 690.3500 ;
      RECT 0.0000 686.3500 1240.0000 690.0500 ;
      RECT 0.0000 686.0500 1239.3800 686.3500 ;
      RECT 0.0000 682.3500 1240.0000 686.0500 ;
      RECT 0.0000 682.0500 1239.3800 682.3500 ;
      RECT 0.0000 678.3500 1240.0000 682.0500 ;
      RECT 0.0000 678.0500 1239.3800 678.3500 ;
      RECT 0.0000 674.3500 1240.0000 678.0500 ;
      RECT 0.0000 674.0500 1239.3800 674.3500 ;
      RECT 0.0000 670.3500 1240.0000 674.0500 ;
      RECT 0.0000 670.0500 1239.3800 670.3500 ;
      RECT 0.0000 666.3500 1240.0000 670.0500 ;
      RECT 0.0000 666.0500 1239.3800 666.3500 ;
      RECT 0.0000 662.3500 1240.0000 666.0500 ;
      RECT 0.0000 662.0500 1239.3800 662.3500 ;
      RECT 0.0000 658.3500 1240.0000 662.0500 ;
      RECT 0.0000 658.0500 1239.3800 658.3500 ;
      RECT 0.0000 654.3500 1240.0000 658.0500 ;
      RECT 0.0000 654.0500 1239.3800 654.3500 ;
      RECT 0.0000 650.3500 1240.0000 654.0500 ;
      RECT 0.0000 650.0500 1239.3800 650.3500 ;
      RECT 0.0000 646.3500 1240.0000 650.0500 ;
      RECT 0.0000 646.0500 1239.3800 646.3500 ;
      RECT 0.0000 642.3500 1240.0000 646.0500 ;
      RECT 0.0000 642.0500 1239.3800 642.3500 ;
      RECT 0.0000 638.3500 1240.0000 642.0500 ;
      RECT 0.0000 638.0500 1239.3800 638.3500 ;
      RECT 0.0000 634.3500 1240.0000 638.0500 ;
      RECT 0.0000 634.0500 1239.3800 634.3500 ;
      RECT 0.0000 630.3500 1240.0000 634.0500 ;
      RECT 0.0000 630.0500 1239.3800 630.3500 ;
      RECT 0.0000 626.3500 1240.0000 630.0500 ;
      RECT 0.0000 626.0500 1239.3800 626.3500 ;
      RECT 0.0000 625.9500 1240.0000 626.0500 ;
      RECT 0.6200 625.6500 1240.0000 625.9500 ;
      RECT 0.0000 622.3500 1240.0000 625.6500 ;
      RECT 0.0000 622.0500 1239.3800 622.3500 ;
      RECT 0.0000 621.9500 1240.0000 622.0500 ;
      RECT 0.6200 621.6500 1240.0000 621.9500 ;
      RECT 0.0000 618.3500 1240.0000 621.6500 ;
      RECT 0.0000 618.0500 1239.3800 618.3500 ;
      RECT 0.0000 617.9500 1240.0000 618.0500 ;
      RECT 0.6200 617.6500 1240.0000 617.9500 ;
      RECT 0.0000 614.3500 1240.0000 617.6500 ;
      RECT 0.0000 614.0500 1239.3800 614.3500 ;
      RECT 0.0000 613.9500 1240.0000 614.0500 ;
      RECT 0.6200 613.6500 1240.0000 613.9500 ;
      RECT 0.0000 610.3500 1240.0000 613.6500 ;
      RECT 0.0000 610.0500 1239.3800 610.3500 ;
      RECT 0.0000 606.3500 1240.0000 610.0500 ;
      RECT 0.0000 606.0500 1239.3800 606.3500 ;
      RECT 0.0000 602.3500 1240.0000 606.0500 ;
      RECT 0.0000 602.0500 1239.3800 602.3500 ;
      RECT 0.0000 598.3500 1240.0000 602.0500 ;
      RECT 0.0000 598.0500 1239.3800 598.3500 ;
      RECT 0.0000 594.3500 1240.0000 598.0500 ;
      RECT 0.0000 594.0500 1239.3800 594.3500 ;
      RECT 0.0000 590.3500 1240.0000 594.0500 ;
      RECT 0.0000 590.0500 1239.3800 590.3500 ;
      RECT 0.0000 586.3500 1240.0000 590.0500 ;
      RECT 0.0000 586.0500 1239.3800 586.3500 ;
      RECT 0.0000 582.3500 1240.0000 586.0500 ;
      RECT 0.0000 582.0500 1239.3800 582.3500 ;
      RECT 0.0000 578.3500 1240.0000 582.0500 ;
      RECT 0.0000 578.0500 1239.3800 578.3500 ;
      RECT 0.0000 574.3500 1240.0000 578.0500 ;
      RECT 0.0000 574.0500 1239.3800 574.3500 ;
      RECT 0.0000 570.3500 1240.0000 574.0500 ;
      RECT 0.0000 570.0500 1239.3800 570.3500 ;
      RECT 0.0000 566.3500 1240.0000 570.0500 ;
      RECT 0.0000 566.0500 1239.3800 566.3500 ;
      RECT 0.0000 562.3500 1240.0000 566.0500 ;
      RECT 0.0000 562.0500 1239.3800 562.3500 ;
      RECT 0.0000 558.3500 1240.0000 562.0500 ;
      RECT 0.0000 558.0500 1239.3800 558.3500 ;
      RECT 0.0000 554.3500 1240.0000 558.0500 ;
      RECT 0.0000 554.0500 1239.3800 554.3500 ;
      RECT 0.0000 550.3500 1240.0000 554.0500 ;
      RECT 0.0000 550.0500 1239.3800 550.3500 ;
      RECT 0.0000 546.3500 1240.0000 550.0500 ;
      RECT 0.0000 546.0500 1239.3800 546.3500 ;
      RECT 0.0000 542.3500 1240.0000 546.0500 ;
      RECT 0.0000 542.0500 1239.3800 542.3500 ;
      RECT 0.0000 538.3500 1240.0000 542.0500 ;
      RECT 0.0000 538.0500 1239.3800 538.3500 ;
      RECT 0.0000 534.3500 1240.0000 538.0500 ;
      RECT 0.0000 534.0500 1239.3800 534.3500 ;
      RECT 0.0000 0.0000 1240.0000 534.0500 ;
    LAYER M4 ;
      RECT 938.0500 1239.3800 1240.0000 1240.0000 ;
      RECT 934.0500 1239.3800 937.7500 1240.0000 ;
      RECT 930.0500 1239.3800 933.7500 1240.0000 ;
      RECT 926.0500 1239.3800 929.7500 1240.0000 ;
      RECT 922.0500 1239.3800 925.7500 1240.0000 ;
      RECT 918.0500 1239.3800 921.7500 1240.0000 ;
      RECT 914.0500 1239.3800 917.7500 1240.0000 ;
      RECT 910.0500 1239.3800 913.7500 1240.0000 ;
      RECT 906.0500 1239.3800 909.7500 1240.0000 ;
      RECT 902.0500 1239.3800 905.7500 1240.0000 ;
      RECT 898.0500 1239.3800 901.7500 1240.0000 ;
      RECT 894.0500 1239.3800 897.7500 1240.0000 ;
      RECT 890.0500 1239.3800 893.7500 1240.0000 ;
      RECT 886.0500 1239.3800 889.7500 1240.0000 ;
      RECT 882.0500 1239.3800 885.7500 1240.0000 ;
      RECT 878.0500 1239.3800 881.7500 1240.0000 ;
      RECT 874.0500 1239.3800 877.7500 1240.0000 ;
      RECT 870.0500 1239.3800 873.7500 1240.0000 ;
      RECT 866.0500 1239.3800 869.7500 1240.0000 ;
      RECT 862.0500 1239.3800 865.7500 1240.0000 ;
      RECT 858.0500 1239.3800 861.7500 1240.0000 ;
      RECT 854.0500 1239.3800 857.7500 1240.0000 ;
      RECT 850.0500 1239.3800 853.7500 1240.0000 ;
      RECT 846.0500 1239.3800 849.7500 1240.0000 ;
      RECT 842.0500 1239.3800 845.7500 1240.0000 ;
      RECT 838.0500 1239.3800 841.7500 1240.0000 ;
      RECT 834.0500 1239.3800 837.7500 1240.0000 ;
      RECT 830.0500 1239.3800 833.7500 1240.0000 ;
      RECT 826.0500 1239.3800 829.7500 1240.0000 ;
      RECT 822.0500 1239.3800 825.7500 1240.0000 ;
      RECT 818.0500 1239.3800 821.7500 1240.0000 ;
      RECT 814.0500 1239.3800 817.7500 1240.0000 ;
      RECT 810.0500 1239.3800 813.7500 1240.0000 ;
      RECT 806.0500 1239.3800 809.7500 1240.0000 ;
      RECT 802.0500 1239.3800 805.7500 1240.0000 ;
      RECT 798.0500 1239.3800 801.7500 1240.0000 ;
      RECT 794.0500 1239.3800 797.7500 1240.0000 ;
      RECT 790.0500 1239.3800 793.7500 1240.0000 ;
      RECT 786.0500 1239.3800 789.7500 1240.0000 ;
      RECT 782.0500 1239.3800 785.7500 1240.0000 ;
      RECT 778.0500 1239.3800 781.7500 1240.0000 ;
      RECT 774.0500 1239.3800 777.7500 1240.0000 ;
      RECT 770.0500 1239.3800 773.7500 1240.0000 ;
      RECT 766.0500 1239.3800 769.7500 1240.0000 ;
      RECT 762.0500 1239.3800 765.7500 1240.0000 ;
      RECT 758.0500 1239.3800 761.7500 1240.0000 ;
      RECT 754.0500 1239.3800 757.7500 1240.0000 ;
      RECT 750.0500 1239.3800 753.7500 1240.0000 ;
      RECT 746.0500 1239.3800 749.7500 1240.0000 ;
      RECT 742.0500 1239.3800 745.7500 1240.0000 ;
      RECT 738.0500 1239.3800 741.7500 1240.0000 ;
      RECT 734.0500 1239.3800 737.7500 1240.0000 ;
      RECT 730.0500 1239.3800 733.7500 1240.0000 ;
      RECT 726.0500 1239.3800 729.7500 1240.0000 ;
      RECT 722.0500 1239.3800 725.7500 1240.0000 ;
      RECT 718.0500 1239.3800 721.7500 1240.0000 ;
      RECT 714.0500 1239.3800 717.7500 1240.0000 ;
      RECT 710.0500 1239.3800 713.7500 1240.0000 ;
      RECT 706.0500 1239.3800 709.7500 1240.0000 ;
      RECT 702.0500 1239.3800 705.7500 1240.0000 ;
      RECT 698.0500 1239.3800 701.7500 1240.0000 ;
      RECT 694.0500 1239.3800 697.7500 1240.0000 ;
      RECT 690.0500 1239.3800 693.7500 1240.0000 ;
      RECT 686.0500 1239.3800 689.7500 1240.0000 ;
      RECT 682.0500 1239.3800 685.7500 1240.0000 ;
      RECT 678.0500 1239.3800 681.7500 1240.0000 ;
      RECT 674.0500 1239.3800 677.7500 1240.0000 ;
      RECT 670.0500 1239.3800 673.7500 1240.0000 ;
      RECT 666.0500 1239.3800 669.7500 1240.0000 ;
      RECT 662.0500 1239.3800 665.7500 1240.0000 ;
      RECT 658.0500 1239.3800 661.7500 1240.0000 ;
      RECT 654.0500 1239.3800 657.7500 1240.0000 ;
      RECT 650.0500 1239.3800 653.7500 1240.0000 ;
      RECT 646.0500 1239.3800 649.7500 1240.0000 ;
      RECT 642.0500 1239.3800 645.7500 1240.0000 ;
      RECT 638.0500 1239.3800 641.7500 1240.0000 ;
      RECT 634.0500 1239.3800 637.7500 1240.0000 ;
      RECT 630.0500 1239.3800 633.7500 1240.0000 ;
      RECT 626.0500 1239.3800 629.7500 1240.0000 ;
      RECT 622.0500 1239.3800 625.7500 1240.0000 ;
      RECT 618.0500 1239.3800 621.7500 1240.0000 ;
      RECT 614.0500 1239.3800 617.7500 1240.0000 ;
      RECT 610.0500 1239.3800 613.7500 1240.0000 ;
      RECT 606.0500 1239.3800 609.7500 1240.0000 ;
      RECT 602.0500 1239.3800 605.7500 1240.0000 ;
      RECT 598.0500 1239.3800 601.7500 1240.0000 ;
      RECT 594.0500 1239.3800 597.7500 1240.0000 ;
      RECT 590.0500 1239.3800 593.7500 1240.0000 ;
      RECT 586.0500 1239.3800 589.7500 1240.0000 ;
      RECT 582.0500 1239.3800 585.7500 1240.0000 ;
      RECT 578.0500 1239.3800 581.7500 1240.0000 ;
      RECT 574.0500 1239.3800 577.7500 1240.0000 ;
      RECT 570.0500 1239.3800 573.7500 1240.0000 ;
      RECT 566.0500 1239.3800 569.7500 1240.0000 ;
      RECT 562.0500 1239.3800 565.7500 1240.0000 ;
      RECT 558.0500 1239.3800 561.7500 1240.0000 ;
      RECT 554.0500 1239.3800 557.7500 1240.0000 ;
      RECT 550.0500 1239.3800 553.7500 1240.0000 ;
      RECT 546.0500 1239.3800 549.7500 1240.0000 ;
      RECT 542.0500 1239.3800 545.7500 1240.0000 ;
      RECT 538.0500 1239.3800 541.7500 1240.0000 ;
      RECT 534.0500 1239.3800 537.7500 1240.0000 ;
      RECT 530.0500 1239.3800 533.7500 1240.0000 ;
      RECT 526.0500 1239.3800 529.7500 1240.0000 ;
      RECT 522.0500 1239.3800 525.7500 1240.0000 ;
      RECT 518.0500 1239.3800 521.7500 1240.0000 ;
      RECT 514.0500 1239.3800 517.7500 1240.0000 ;
      RECT 510.0500 1239.3800 513.7500 1240.0000 ;
      RECT 506.0500 1239.3800 509.7500 1240.0000 ;
      RECT 502.0500 1239.3800 505.7500 1240.0000 ;
      RECT 498.0500 1239.3800 501.7500 1240.0000 ;
      RECT 494.0500 1239.3800 497.7500 1240.0000 ;
      RECT 490.0500 1239.3800 493.7500 1240.0000 ;
      RECT 486.0500 1239.3800 489.7500 1240.0000 ;
      RECT 482.0500 1239.3800 485.7500 1240.0000 ;
      RECT 478.0500 1239.3800 481.7500 1240.0000 ;
      RECT 474.0500 1239.3800 477.7500 1240.0000 ;
      RECT 470.0500 1239.3800 473.7500 1240.0000 ;
      RECT 466.0500 1239.3800 469.7500 1240.0000 ;
      RECT 462.0500 1239.3800 465.7500 1240.0000 ;
      RECT 458.0500 1239.3800 461.7500 1240.0000 ;
      RECT 454.0500 1239.3800 457.7500 1240.0000 ;
      RECT 450.0500 1239.3800 453.7500 1240.0000 ;
      RECT 446.0500 1239.3800 449.7500 1240.0000 ;
      RECT 442.0500 1239.3800 445.7500 1240.0000 ;
      RECT 438.0500 1239.3800 441.7500 1240.0000 ;
      RECT 434.0500 1239.3800 437.7500 1240.0000 ;
      RECT 430.0500 1239.3800 433.7500 1240.0000 ;
      RECT 426.0500 1239.3800 429.7500 1240.0000 ;
      RECT 422.0500 1239.3800 425.7500 1240.0000 ;
      RECT 418.0500 1239.3800 421.7500 1240.0000 ;
      RECT 414.0500 1239.3800 417.7500 1240.0000 ;
      RECT 410.0500 1239.3800 413.7500 1240.0000 ;
      RECT 406.0500 1239.3800 409.7500 1240.0000 ;
      RECT 402.0500 1239.3800 405.7500 1240.0000 ;
      RECT 398.0500 1239.3800 401.7500 1240.0000 ;
      RECT 394.0500 1239.3800 397.7500 1240.0000 ;
      RECT 390.0500 1239.3800 393.7500 1240.0000 ;
      RECT 386.0500 1239.3800 389.7500 1240.0000 ;
      RECT 382.0500 1239.3800 385.7500 1240.0000 ;
      RECT 378.0500 1239.3800 381.7500 1240.0000 ;
      RECT 374.0500 1239.3800 377.7500 1240.0000 ;
      RECT 370.0500 1239.3800 373.7500 1240.0000 ;
      RECT 366.0500 1239.3800 369.7500 1240.0000 ;
      RECT 362.0500 1239.3800 365.7500 1240.0000 ;
      RECT 358.0500 1239.3800 361.7500 1240.0000 ;
      RECT 354.0500 1239.3800 357.7500 1240.0000 ;
      RECT 350.0500 1239.3800 353.7500 1240.0000 ;
      RECT 346.0500 1239.3800 349.7500 1240.0000 ;
      RECT 342.0500 1239.3800 345.7500 1240.0000 ;
      RECT 338.0500 1239.3800 341.7500 1240.0000 ;
      RECT 334.0500 1239.3800 337.7500 1240.0000 ;
      RECT 330.0500 1239.3800 333.7500 1240.0000 ;
      RECT 326.0500 1239.3800 329.7500 1240.0000 ;
      RECT 322.0500 1239.3800 325.7500 1240.0000 ;
      RECT 318.0500 1239.3800 321.7500 1240.0000 ;
      RECT 314.0500 1239.3800 317.7500 1240.0000 ;
      RECT 310.0500 1239.3800 313.7500 1240.0000 ;
      RECT 306.0500 1239.3800 309.7500 1240.0000 ;
      RECT 302.0500 1239.3800 305.7500 1240.0000 ;
      RECT 0.0000 1239.3800 301.7500 1240.0000 ;
      RECT 0.0000 1116.4200 1240.0000 1239.3800 ;
      RECT 772.6600 1115.1000 1240.0000 1116.4200 ;
      RECT 98.1600 1115.1000 771.8400 1116.4200 ;
      RECT 0.0000 1115.1000 97.3400 1116.4200 ;
      RECT 0.0000 1111.4200 1240.0000 1115.1000 ;
      RECT 99.1600 1110.3250 770.8400 1111.4200 ;
      RECT 238.9600 1110.1600 770.8400 1110.3250 ;
      RECT 771.6600 1110.1000 1240.0000 1111.4200 ;
      RECT 251.9600 1110.1000 770.8400 1110.1600 ;
      RECT 99.1600 1110.1000 237.6400 1110.3250 ;
      RECT 0.0000 1110.1000 98.3400 1111.4200 ;
      RECT 238.9600 1107.0050 250.6400 1110.1600 ;
      RECT 0.0000 1107.0050 237.6400 1110.1000 ;
      RECT 251.9600 1106.8400 1240.0000 1110.1000 ;
      RECT 0.0000 1106.8400 250.6400 1107.0050 ;
      RECT 0.0000 1067.4300 1240.0000 1106.8400 ;
      RECT 760.5000 1067.0900 1240.0000 1067.4300 ;
      RECT 0.0000 1067.0900 122.5000 1067.4300 ;
      RECT 772.6600 1065.7700 1240.0000 1067.0900 ;
      RECT 760.5000 1065.7700 771.8400 1067.0900 ;
      RECT 98.1600 1065.7700 122.5000 1067.0900 ;
      RECT 0.0000 1065.7700 97.3400 1067.0900 ;
      RECT 760.5000 1065.4300 1240.0000 1065.7700 ;
      RECT 633.7000 1065.4300 756.5000 1067.4300 ;
      RECT 506.9000 1065.4300 629.7000 1067.4300 ;
      RECT 380.1000 1065.4300 502.9000 1067.4300 ;
      RECT 253.3000 1065.4300 376.1000 1067.4300 ;
      RECT 126.5000 1065.4300 249.3000 1067.4300 ;
      RECT 0.0000 1065.4300 122.5000 1065.7700 ;
      RECT 0.0000 1062.4300 1240.0000 1065.4300 ;
      RECT 747.5000 1062.0900 1240.0000 1062.4300 ;
      RECT 0.0000 1062.0900 109.5000 1062.4300 ;
      RECT 771.6600 1060.7700 1240.0000 1062.0900 ;
      RECT 747.5000 1060.7700 770.8400 1062.0900 ;
      RECT 99.1600 1060.7700 109.5000 1062.0900 ;
      RECT 0.0000 1060.7700 98.3400 1062.0900 ;
      RECT 747.5000 1060.4300 1240.0000 1060.7700 ;
      RECT 620.7000 1060.4300 743.5000 1062.4300 ;
      RECT 493.9000 1060.4300 616.7000 1062.4300 ;
      RECT 367.1000 1060.4300 489.9000 1062.4300 ;
      RECT 240.3000 1060.4300 363.1000 1062.4300 ;
      RECT 113.5000 1060.4300 236.3000 1062.4300 ;
      RECT 0.0000 1060.4300 109.5000 1060.7700 ;
      RECT 0.0000 1018.1000 1240.0000 1060.4300 ;
      RECT 760.5000 1017.7600 1240.0000 1018.1000 ;
      RECT 0.0000 1017.7600 122.5000 1018.1000 ;
      RECT 772.6600 1016.4400 1240.0000 1017.7600 ;
      RECT 760.5000 1016.4400 771.8400 1017.7600 ;
      RECT 98.1600 1016.4400 122.5000 1017.7600 ;
      RECT 0.0000 1016.4400 97.3400 1017.7600 ;
      RECT 760.5000 1016.1000 1240.0000 1016.4400 ;
      RECT 633.7000 1016.1000 756.5000 1018.1000 ;
      RECT 506.9000 1016.1000 629.7000 1018.1000 ;
      RECT 380.1000 1016.1000 502.9000 1018.1000 ;
      RECT 253.3000 1016.1000 376.1000 1018.1000 ;
      RECT 126.5000 1016.1000 249.3000 1018.1000 ;
      RECT 0.0000 1016.1000 122.5000 1016.4400 ;
      RECT 0.0000 1013.1000 1240.0000 1016.1000 ;
      RECT 747.5000 1012.7600 1240.0000 1013.1000 ;
      RECT 0.0000 1012.7600 109.5000 1013.1000 ;
      RECT 771.6600 1011.4400 1240.0000 1012.7600 ;
      RECT 747.5000 1011.4400 770.8400 1012.7600 ;
      RECT 99.1600 1011.4400 109.5000 1012.7600 ;
      RECT 0.0000 1011.4400 98.3400 1012.7600 ;
      RECT 747.5000 1011.1000 1240.0000 1011.4400 ;
      RECT 620.7000 1011.1000 743.5000 1013.1000 ;
      RECT 493.9000 1011.1000 616.7000 1013.1000 ;
      RECT 367.1000 1011.1000 489.9000 1013.1000 ;
      RECT 240.3000 1011.1000 363.1000 1013.1000 ;
      RECT 113.5000 1011.1000 236.3000 1013.1000 ;
      RECT 0.0000 1011.1000 109.5000 1011.4400 ;
      RECT 0.0000 968.7700 1240.0000 1011.1000 ;
      RECT 760.5000 968.4300 1240.0000 968.7700 ;
      RECT 0.0000 968.4300 122.5000 968.7700 ;
      RECT 772.6600 967.1100 1240.0000 968.4300 ;
      RECT 760.5000 967.1100 771.8400 968.4300 ;
      RECT 98.1600 967.1100 122.5000 968.4300 ;
      RECT 0.0000 967.1100 97.3400 968.4300 ;
      RECT 760.5000 966.7700 1240.0000 967.1100 ;
      RECT 633.7000 966.7700 756.5000 968.7700 ;
      RECT 506.9000 966.7700 629.7000 968.7700 ;
      RECT 380.1000 966.7700 502.9000 968.7700 ;
      RECT 253.3000 966.7700 376.1000 968.7700 ;
      RECT 126.5000 966.7700 249.3000 968.7700 ;
      RECT 0.0000 966.7700 122.5000 967.1100 ;
      RECT 0.0000 963.7700 1240.0000 966.7700 ;
      RECT 747.5000 963.4300 1240.0000 963.7700 ;
      RECT 0.0000 963.4300 109.5000 963.7700 ;
      RECT 771.6600 962.1100 1240.0000 963.4300 ;
      RECT 747.5000 962.1100 770.8400 963.4300 ;
      RECT 99.1600 962.1100 109.5000 963.4300 ;
      RECT 0.0000 962.1100 98.3400 963.4300 ;
      RECT 747.5000 961.7700 1240.0000 962.1100 ;
      RECT 620.7000 961.7700 743.5000 963.7700 ;
      RECT 493.9000 961.7700 616.7000 963.7700 ;
      RECT 367.1000 961.7700 489.9000 963.7700 ;
      RECT 240.3000 961.7700 363.1000 963.7700 ;
      RECT 113.5000 961.7700 236.3000 963.7700 ;
      RECT 0.0000 961.7700 109.5000 962.1100 ;
      RECT 0.0000 919.4400 1240.0000 961.7700 ;
      RECT 760.5000 919.1000 1240.0000 919.4400 ;
      RECT 0.0000 919.1000 122.5000 919.4400 ;
      RECT 772.6600 917.7800 1240.0000 919.1000 ;
      RECT 760.5000 917.7800 771.8400 919.1000 ;
      RECT 98.1600 917.7800 122.5000 919.1000 ;
      RECT 0.0000 917.7800 97.3400 919.1000 ;
      RECT 760.5000 917.4400 1240.0000 917.7800 ;
      RECT 633.7000 917.4400 756.5000 919.4400 ;
      RECT 506.9000 917.4400 629.7000 919.4400 ;
      RECT 380.1000 917.4400 502.9000 919.4400 ;
      RECT 253.3000 917.4400 376.1000 919.4400 ;
      RECT 126.5000 917.4400 249.3000 919.4400 ;
      RECT 0.0000 917.4400 122.5000 917.7800 ;
      RECT 0.0000 914.4400 1240.0000 917.4400 ;
      RECT 747.5000 914.1000 1240.0000 914.4400 ;
      RECT 0.0000 914.1000 109.5000 914.4400 ;
      RECT 771.6600 912.7800 1240.0000 914.1000 ;
      RECT 747.5000 912.7800 770.8400 914.1000 ;
      RECT 99.1600 912.7800 109.5000 914.1000 ;
      RECT 0.0000 912.7800 98.3400 914.1000 ;
      RECT 747.5000 912.4400 1240.0000 912.7800 ;
      RECT 620.7000 912.4400 743.5000 914.4400 ;
      RECT 493.9000 912.4400 616.7000 914.4400 ;
      RECT 367.1000 912.4400 489.9000 914.4400 ;
      RECT 240.3000 912.4400 363.1000 914.4400 ;
      RECT 113.5000 912.4400 236.3000 914.4400 ;
      RECT 0.0000 912.4400 109.5000 912.7800 ;
      RECT 0.0000 870.1100 1240.0000 912.4400 ;
      RECT 760.5000 869.7700 1240.0000 870.1100 ;
      RECT 0.0000 869.7700 122.5000 870.1100 ;
      RECT 772.6600 868.4500 1240.0000 869.7700 ;
      RECT 760.5000 868.4500 771.8400 869.7700 ;
      RECT 98.1600 868.4500 122.5000 869.7700 ;
      RECT 0.0000 868.4500 97.3400 869.7700 ;
      RECT 760.5000 868.1100 1240.0000 868.4500 ;
      RECT 633.7000 868.1100 756.5000 870.1100 ;
      RECT 506.9000 868.1100 629.7000 870.1100 ;
      RECT 380.1000 868.1100 502.9000 870.1100 ;
      RECT 253.3000 868.1100 376.1000 870.1100 ;
      RECT 126.5000 868.1100 249.3000 870.1100 ;
      RECT 0.0000 868.1100 122.5000 868.4500 ;
      RECT 0.0000 865.1100 1240.0000 868.1100 ;
      RECT 747.5000 864.7700 1240.0000 865.1100 ;
      RECT 0.0000 864.7700 109.5000 865.1100 ;
      RECT 771.6600 863.4500 1240.0000 864.7700 ;
      RECT 747.5000 863.4500 770.8400 864.7700 ;
      RECT 99.1600 863.4500 109.5000 864.7700 ;
      RECT 0.0000 863.4500 98.3400 864.7700 ;
      RECT 747.5000 863.1100 1240.0000 863.4500 ;
      RECT 620.7000 863.1100 743.5000 865.1100 ;
      RECT 493.9000 863.1100 616.7000 865.1100 ;
      RECT 367.1000 863.1100 489.9000 865.1100 ;
      RECT 240.3000 863.1100 363.1000 865.1100 ;
      RECT 113.5000 863.1100 236.3000 865.1100 ;
      RECT 0.0000 863.1100 109.5000 863.4500 ;
      RECT 0.0000 820.7800 1240.0000 863.1100 ;
      RECT 760.5000 820.4400 1240.0000 820.7800 ;
      RECT 0.0000 820.4400 122.5000 820.7800 ;
      RECT 772.6600 819.1200 1240.0000 820.4400 ;
      RECT 760.5000 819.1200 771.8400 820.4400 ;
      RECT 98.1600 819.1200 122.5000 820.4400 ;
      RECT 0.0000 819.1200 97.3400 820.4400 ;
      RECT 760.5000 818.7800 1240.0000 819.1200 ;
      RECT 633.7000 818.7800 756.5000 820.7800 ;
      RECT 506.9000 818.7800 629.7000 820.7800 ;
      RECT 380.1000 818.7800 502.9000 820.7800 ;
      RECT 253.3000 818.7800 376.1000 820.7800 ;
      RECT 126.5000 818.7800 249.3000 820.7800 ;
      RECT 0.0000 818.7800 122.5000 819.1200 ;
      RECT 0.0000 815.7800 1240.0000 818.7800 ;
      RECT 747.5000 815.4400 1240.0000 815.7800 ;
      RECT 0.0000 815.4400 109.5000 815.7800 ;
      RECT 771.6600 814.1200 1240.0000 815.4400 ;
      RECT 747.5000 814.1200 770.8400 815.4400 ;
      RECT 99.1600 814.1200 109.5000 815.4400 ;
      RECT 0.0000 814.1200 98.3400 815.4400 ;
      RECT 747.5000 813.7800 1240.0000 814.1200 ;
      RECT 620.7000 813.7800 743.5000 815.7800 ;
      RECT 493.9000 813.7800 616.7000 815.7800 ;
      RECT 367.1000 813.7800 489.9000 815.7800 ;
      RECT 240.3000 813.7800 363.1000 815.7800 ;
      RECT 113.5000 813.7800 236.3000 815.7800 ;
      RECT 0.0000 813.7800 109.5000 814.1200 ;
      RECT 0.0000 771.4500 1240.0000 813.7800 ;
      RECT 760.5000 771.1100 1240.0000 771.4500 ;
      RECT 0.0000 771.1100 122.5000 771.4500 ;
      RECT 772.6600 769.7900 1240.0000 771.1100 ;
      RECT 760.5000 769.7900 771.8400 771.1100 ;
      RECT 98.1600 769.7900 122.5000 771.1100 ;
      RECT 0.0000 769.7900 97.3400 771.1100 ;
      RECT 760.5000 769.4500 1240.0000 769.7900 ;
      RECT 633.7000 769.4500 756.5000 771.4500 ;
      RECT 506.9000 769.4500 629.7000 771.4500 ;
      RECT 380.1000 769.4500 502.9000 771.4500 ;
      RECT 253.3000 769.4500 376.1000 771.4500 ;
      RECT 126.5000 769.4500 249.3000 771.4500 ;
      RECT 0.0000 769.4500 122.5000 769.7900 ;
      RECT 0.0000 766.4500 1240.0000 769.4500 ;
      RECT 747.5000 766.1100 1240.0000 766.4500 ;
      RECT 0.0000 766.1100 109.5000 766.4500 ;
      RECT 771.6600 764.7900 1240.0000 766.1100 ;
      RECT 747.5000 764.7900 770.8400 766.1100 ;
      RECT 99.1600 764.7900 109.5000 766.1100 ;
      RECT 0.0000 764.7900 98.3400 766.1100 ;
      RECT 747.5000 764.4500 1240.0000 764.7900 ;
      RECT 620.7000 764.4500 743.5000 766.4500 ;
      RECT 493.9000 764.4500 616.7000 766.4500 ;
      RECT 367.1000 764.4500 489.9000 766.4500 ;
      RECT 240.3000 764.4500 363.1000 766.4500 ;
      RECT 113.5000 764.4500 236.3000 766.4500 ;
      RECT 0.0000 764.4500 109.5000 764.7900 ;
      RECT 0.0000 722.1200 1240.0000 764.4500 ;
      RECT 760.5000 721.7800 1240.0000 722.1200 ;
      RECT 0.0000 721.7800 122.5000 722.1200 ;
      RECT 772.6600 720.4600 1240.0000 721.7800 ;
      RECT 760.5000 720.4600 771.8400 721.7800 ;
      RECT 98.1600 720.4600 122.5000 721.7800 ;
      RECT 0.0000 720.4600 97.3400 721.7800 ;
      RECT 760.5000 720.1200 1240.0000 720.4600 ;
      RECT 633.7000 720.1200 756.5000 722.1200 ;
      RECT 506.9000 720.1200 629.7000 722.1200 ;
      RECT 380.1000 720.1200 502.9000 722.1200 ;
      RECT 253.3000 720.1200 376.1000 722.1200 ;
      RECT 126.5000 720.1200 249.3000 722.1200 ;
      RECT 0.0000 720.1200 122.5000 720.4600 ;
      RECT 0.0000 717.1200 1240.0000 720.1200 ;
      RECT 747.5000 716.7800 1240.0000 717.1200 ;
      RECT 0.0000 716.7800 109.5000 717.1200 ;
      RECT 771.6600 715.4600 1240.0000 716.7800 ;
      RECT 747.5000 715.4600 770.8400 716.7800 ;
      RECT 99.1600 715.4600 109.5000 716.7800 ;
      RECT 0.0000 715.4600 98.3400 716.7800 ;
      RECT 747.5000 715.1200 1240.0000 715.4600 ;
      RECT 620.7000 715.1200 743.5000 717.1200 ;
      RECT 493.9000 715.1200 616.7000 717.1200 ;
      RECT 367.1000 715.1200 489.9000 717.1200 ;
      RECT 240.3000 715.1200 363.1000 717.1200 ;
      RECT 113.5000 715.1200 236.3000 717.1200 ;
      RECT 0.0000 715.1200 109.5000 715.4600 ;
      RECT 0.0000 672.7900 1240.0000 715.1200 ;
      RECT 760.5000 672.4500 1240.0000 672.7900 ;
      RECT 0.0000 672.4500 122.5000 672.7900 ;
      RECT 772.6600 671.1300 1240.0000 672.4500 ;
      RECT 760.5000 671.1300 771.8400 672.4500 ;
      RECT 98.1600 671.1300 122.5000 672.4500 ;
      RECT 0.0000 671.1300 97.3400 672.4500 ;
      RECT 760.5000 670.7900 1240.0000 671.1300 ;
      RECT 633.7000 670.7900 756.5000 672.7900 ;
      RECT 506.9000 670.7900 629.7000 672.7900 ;
      RECT 380.1000 670.7900 502.9000 672.7900 ;
      RECT 253.3000 670.7900 376.1000 672.7900 ;
      RECT 126.5000 670.7900 249.3000 672.7900 ;
      RECT 0.0000 670.7900 122.5000 671.1300 ;
      RECT 0.0000 667.7900 1240.0000 670.7900 ;
      RECT 747.5000 667.4500 1240.0000 667.7900 ;
      RECT 0.0000 667.4500 109.5000 667.7900 ;
      RECT 771.6600 666.1300 1240.0000 667.4500 ;
      RECT 747.5000 666.1300 770.8400 667.4500 ;
      RECT 99.1600 666.1300 109.5000 667.4500 ;
      RECT 0.0000 666.1300 98.3400 667.4500 ;
      RECT 747.5000 665.7900 1240.0000 666.1300 ;
      RECT 620.7000 665.7900 743.5000 667.7900 ;
      RECT 493.9000 665.7900 616.7000 667.7900 ;
      RECT 367.1000 665.7900 489.9000 667.7900 ;
      RECT 240.3000 665.7900 363.1000 667.7900 ;
      RECT 113.5000 665.7900 236.3000 667.7900 ;
      RECT 0.0000 665.7900 109.5000 666.1300 ;
      RECT 0.0000 623.4600 1240.0000 665.7900 ;
      RECT 760.5000 623.1200 1240.0000 623.4600 ;
      RECT 0.0000 623.1200 122.5000 623.4600 ;
      RECT 772.6600 621.8000 1240.0000 623.1200 ;
      RECT 760.5000 621.8000 771.8400 623.1200 ;
      RECT 98.1600 621.8000 122.5000 623.1200 ;
      RECT 0.0000 621.8000 97.3400 623.1200 ;
      RECT 760.5000 621.4600 1240.0000 621.8000 ;
      RECT 633.7000 621.4600 756.5000 623.4600 ;
      RECT 506.9000 621.4600 629.7000 623.4600 ;
      RECT 380.1000 621.4600 502.9000 623.4600 ;
      RECT 253.3000 621.4600 376.1000 623.4600 ;
      RECT 126.5000 621.4600 249.3000 623.4600 ;
      RECT 0.0000 621.4600 122.5000 621.8000 ;
      RECT 0.0000 618.4600 1240.0000 621.4600 ;
      RECT 747.5000 618.1200 1240.0000 618.4600 ;
      RECT 0.0000 618.1200 109.5000 618.4600 ;
      RECT 771.6600 616.8000 1240.0000 618.1200 ;
      RECT 747.5000 616.8000 770.8400 618.1200 ;
      RECT 99.1600 616.8000 109.5000 618.1200 ;
      RECT 0.0000 616.8000 98.3400 618.1200 ;
      RECT 747.5000 616.4600 1240.0000 616.8000 ;
      RECT 620.7000 616.4600 743.5000 618.4600 ;
      RECT 493.9000 616.4600 616.7000 618.4600 ;
      RECT 367.1000 616.4600 489.9000 618.4600 ;
      RECT 240.3000 616.4600 363.1000 618.4600 ;
      RECT 113.5000 616.4600 236.3000 618.4600 ;
      RECT 0.0000 616.4600 109.5000 616.8000 ;
      RECT 0.0000 574.1300 1240.0000 616.4600 ;
      RECT 760.5000 573.7900 1240.0000 574.1300 ;
      RECT 0.0000 573.7900 122.5000 574.1300 ;
      RECT 772.6600 572.4700 1240.0000 573.7900 ;
      RECT 760.5000 572.4700 771.8400 573.7900 ;
      RECT 98.1600 572.4700 122.5000 573.7900 ;
      RECT 0.0000 572.4700 97.3400 573.7900 ;
      RECT 760.5000 572.1300 1240.0000 572.4700 ;
      RECT 633.7000 572.1300 756.5000 574.1300 ;
      RECT 506.9000 572.1300 629.7000 574.1300 ;
      RECT 380.1000 572.1300 502.9000 574.1300 ;
      RECT 253.3000 572.1300 376.1000 574.1300 ;
      RECT 126.5000 572.1300 249.3000 574.1300 ;
      RECT 0.0000 572.1300 122.5000 572.4700 ;
      RECT 0.0000 569.1300 1240.0000 572.1300 ;
      RECT 747.5000 568.7900 1240.0000 569.1300 ;
      RECT 0.0000 568.7900 109.5000 569.1300 ;
      RECT 771.6600 567.4700 1240.0000 568.7900 ;
      RECT 747.5000 567.4700 770.8400 568.7900 ;
      RECT 99.1600 567.4700 109.5000 568.7900 ;
      RECT 0.0000 567.4700 98.3400 568.7900 ;
      RECT 747.5000 567.1300 1240.0000 567.4700 ;
      RECT 620.7000 567.1300 743.5000 569.1300 ;
      RECT 493.9000 567.1300 616.7000 569.1300 ;
      RECT 367.1000 567.1300 489.9000 569.1300 ;
      RECT 240.3000 567.1300 363.1000 569.1300 ;
      RECT 113.5000 567.1300 236.3000 569.1300 ;
      RECT 0.0000 567.1300 109.5000 567.4700 ;
      RECT 0.0000 524.8000 1240.0000 567.1300 ;
      RECT 760.5000 524.4600 1240.0000 524.8000 ;
      RECT 0.0000 524.4600 122.5000 524.8000 ;
      RECT 772.6600 523.1400 1240.0000 524.4600 ;
      RECT 760.5000 523.1400 771.8400 524.4600 ;
      RECT 98.1600 523.1400 122.5000 524.4600 ;
      RECT 0.0000 523.1400 97.3400 524.4600 ;
      RECT 760.5000 522.8000 1240.0000 523.1400 ;
      RECT 633.7000 522.8000 756.5000 524.8000 ;
      RECT 506.9000 522.8000 629.7000 524.8000 ;
      RECT 380.1000 522.8000 502.9000 524.8000 ;
      RECT 253.3000 522.8000 376.1000 524.8000 ;
      RECT 126.5000 522.8000 249.3000 524.8000 ;
      RECT 0.0000 522.8000 122.5000 523.1400 ;
      RECT 0.0000 519.8000 1240.0000 522.8000 ;
      RECT 747.5000 519.4600 1240.0000 519.8000 ;
      RECT 0.0000 519.4600 109.5000 519.8000 ;
      RECT 771.6600 518.1400 1240.0000 519.4600 ;
      RECT 747.5000 518.1400 770.8400 519.4600 ;
      RECT 99.1600 518.1400 109.5000 519.4600 ;
      RECT 0.0000 518.1400 98.3400 519.4600 ;
      RECT 747.5000 517.8000 1240.0000 518.1400 ;
      RECT 620.7000 517.8000 743.5000 519.8000 ;
      RECT 493.9000 517.8000 616.7000 519.8000 ;
      RECT 367.1000 517.8000 489.9000 519.8000 ;
      RECT 240.3000 517.8000 363.1000 519.8000 ;
      RECT 113.5000 517.8000 236.3000 519.8000 ;
      RECT 0.0000 517.8000 109.5000 518.1400 ;
      RECT 0.0000 475.4700 1240.0000 517.8000 ;
      RECT 760.5000 475.1300 1240.0000 475.4700 ;
      RECT 0.0000 475.1300 122.5000 475.4700 ;
      RECT 772.6600 473.8100 1240.0000 475.1300 ;
      RECT 760.5000 473.8100 771.8400 475.1300 ;
      RECT 98.1600 473.8100 122.5000 475.1300 ;
      RECT 0.0000 473.8100 97.3400 475.1300 ;
      RECT 760.5000 473.4700 1240.0000 473.8100 ;
      RECT 633.7000 473.4700 756.5000 475.4700 ;
      RECT 506.9000 473.4700 629.7000 475.4700 ;
      RECT 380.1000 473.4700 502.9000 475.4700 ;
      RECT 253.3000 473.4700 376.1000 475.4700 ;
      RECT 126.5000 473.4700 249.3000 475.4700 ;
      RECT 0.0000 473.4700 122.5000 473.8100 ;
      RECT 0.0000 470.4700 1240.0000 473.4700 ;
      RECT 747.5000 470.1300 1240.0000 470.4700 ;
      RECT 0.0000 470.1300 109.5000 470.4700 ;
      RECT 771.6600 468.8100 1240.0000 470.1300 ;
      RECT 747.5000 468.8100 770.8400 470.1300 ;
      RECT 99.1600 468.8100 109.5000 470.1300 ;
      RECT 0.0000 468.8100 98.3400 470.1300 ;
      RECT 747.5000 468.4700 1240.0000 468.8100 ;
      RECT 620.7000 468.4700 743.5000 470.4700 ;
      RECT 493.9000 468.4700 616.7000 470.4700 ;
      RECT 367.1000 468.4700 489.9000 470.4700 ;
      RECT 240.3000 468.4700 363.1000 470.4700 ;
      RECT 113.5000 468.4700 236.3000 470.4700 ;
      RECT 0.0000 468.4700 109.5000 468.8100 ;
      RECT 0.0000 376.4700 1240.0000 468.4700 ;
      RECT 727.6600 375.1500 1240.0000 376.4700 ;
      RECT 448.1600 375.1500 726.8400 376.4700 ;
      RECT 377.6600 375.1500 447.3400 376.4700 ;
      RECT 98.1600 375.1500 376.8400 376.4700 ;
      RECT 0.0000 375.1500 97.3400 376.4700 ;
      RECT 0.0000 371.4700 1240.0000 375.1500 ;
      RECT 726.6600 370.1500 1240.0000 371.4700 ;
      RECT 449.1600 370.1500 725.8400 371.4700 ;
      RECT 376.6600 370.1500 448.3400 371.4700 ;
      RECT 99.1600 370.1500 375.8400 371.4700 ;
      RECT 0.0000 370.1500 98.3400 371.4700 ;
      RECT 0.0000 327.1400 1240.0000 370.1500 ;
      RECT 727.6600 325.8200 1240.0000 327.1400 ;
      RECT 448.1600 325.8200 726.8400 327.1400 ;
      RECT 377.6600 325.8200 447.3400 327.1400 ;
      RECT 98.1600 325.8200 376.8400 327.1400 ;
      RECT 0.0000 325.8200 97.3400 327.1400 ;
      RECT 0.0000 322.1400 1240.0000 325.8200 ;
      RECT 726.6600 320.8200 1240.0000 322.1400 ;
      RECT 449.1600 320.8200 725.8400 322.1400 ;
      RECT 376.6600 320.8200 448.3400 322.1400 ;
      RECT 99.1600 320.8200 375.8400 322.1400 ;
      RECT 0.0000 320.8200 98.3400 322.1400 ;
      RECT 0.0000 283.0100 1240.0000 320.8200 ;
      RECT 173.3350 282.6700 519.3350 283.0100 ;
      RECT 0.0000 282.6700 169.3350 283.0100 ;
      RECT 449.1600 281.8500 519.3350 282.6700 ;
      RECT 173.3350 281.8500 448.3400 282.6700 ;
      RECT 99.1600 281.8500 169.3350 282.6700 ;
      RECT 0.0000 281.8500 98.3400 282.6700 ;
      RECT 523.3350 281.5100 1240.0000 283.0100 ;
      RECT 173.3350 281.5100 519.3350 281.8500 ;
      RECT 0.0000 281.5100 169.3350 281.8500 ;
      RECT 0.0000 277.8100 1240.0000 281.5100 ;
      RECT 727.6600 276.4900 1240.0000 277.8100 ;
      RECT 448.1600 276.4900 726.8400 277.8100 ;
      RECT 377.6600 276.4900 447.3400 277.8100 ;
      RECT 98.1600 276.4900 376.8400 277.8100 ;
      RECT 0.0000 276.4900 97.3400 277.8100 ;
      RECT 0.0000 272.8100 1240.0000 276.4900 ;
      RECT 726.6600 271.4900 1240.0000 272.8100 ;
      RECT 449.1600 271.4900 725.8400 272.8100 ;
      RECT 376.6600 271.4900 448.3400 272.8100 ;
      RECT 99.1600 271.4900 375.8400 272.8100 ;
      RECT 0.0000 271.4900 98.3400 272.8100 ;
      RECT 0.0000 228.4800 1240.0000 271.4900 ;
      RECT 727.6600 227.1600 1240.0000 228.4800 ;
      RECT 448.1600 227.1600 726.8400 228.4800 ;
      RECT 377.6600 227.1600 447.3400 228.4800 ;
      RECT 98.1600 227.1600 376.8400 228.4800 ;
      RECT 0.0000 227.1600 97.3400 228.4800 ;
      RECT 0.0000 223.4800 1240.0000 227.1600 ;
      RECT 726.6600 222.1600 1240.0000 223.4800 ;
      RECT 449.1600 222.1600 725.8400 223.4800 ;
      RECT 376.6600 222.1600 448.3400 223.4800 ;
      RECT 99.1600 222.1600 375.8400 223.4800 ;
      RECT 0.0000 222.1600 98.3400 223.4800 ;
      RECT 0.0000 179.1500 1240.0000 222.1600 ;
      RECT 727.6600 177.8300 1240.0000 179.1500 ;
      RECT 448.1600 177.8300 726.8400 179.1500 ;
      RECT 377.6600 177.8300 447.3400 179.1500 ;
      RECT 98.1600 177.8300 376.8400 179.1500 ;
      RECT 0.0000 177.8300 97.3400 179.1500 ;
      RECT 0.0000 174.1500 1240.0000 177.8300 ;
      RECT 726.6600 172.8300 1240.0000 174.1500 ;
      RECT 449.1600 172.8300 725.8400 174.1500 ;
      RECT 376.6600 172.8300 448.3400 174.1500 ;
      RECT 99.1600 172.8300 375.8400 174.1500 ;
      RECT 0.0000 172.8300 98.3400 174.1500 ;
      RECT 0.0000 172.2500 1240.0000 172.8300 ;
      RECT 655.6650 171.9100 1240.0000 172.2500 ;
      RECT 305.6650 171.9100 651.6650 172.2500 ;
      RECT 727.6600 171.0900 1240.0000 171.9100 ;
      RECT 655.6650 171.0900 726.8400 171.9100 ;
      RECT 377.6600 171.0900 651.6650 171.9100 ;
      RECT 305.6650 171.0900 376.8400 171.9100 ;
      RECT 655.6650 170.7500 1240.0000 171.0900 ;
      RECT 305.6650 170.7500 651.6650 171.0900 ;
      RECT 0.0000 170.7500 301.6650 172.2500 ;
      RECT 0.0000 129.8200 1240.0000 170.7500 ;
      RECT 727.6600 128.5000 1240.0000 129.8200 ;
      RECT 448.1600 128.5000 726.8400 129.8200 ;
      RECT 377.6600 128.5000 447.3400 129.8200 ;
      RECT 98.1600 128.5000 376.8400 129.8200 ;
      RECT 0.0000 128.5000 97.3400 129.8200 ;
      RECT 0.0000 124.8200 1240.0000 128.5000 ;
      RECT 726.6600 123.5000 1240.0000 124.8200 ;
      RECT 449.1600 123.5000 725.8400 124.8200 ;
      RECT 376.6600 123.5000 448.3400 124.8200 ;
      RECT 99.1600 123.5000 375.8400 124.8200 ;
      RECT 0.0000 123.5000 98.3400 124.8200 ;
      RECT 0.0000 0.6200 1240.0000 123.5000 ;
      RECT 794.2500 0.0000 1240.0000 0.6200 ;
      RECT 790.2500 0.0000 793.9500 0.6200 ;
      RECT 786.2500 0.0000 789.9500 0.6200 ;
      RECT 782.2500 0.0000 785.9500 0.6200 ;
      RECT 778.2500 0.0000 781.9500 0.6200 ;
      RECT 774.2500 0.0000 777.9500 0.6200 ;
      RECT 770.2500 0.0000 773.9500 0.6200 ;
      RECT 766.2500 0.0000 769.9500 0.6200 ;
      RECT 762.2500 0.0000 765.9500 0.6200 ;
      RECT 758.2500 0.0000 761.9500 0.6200 ;
      RECT 754.2500 0.0000 757.9500 0.6200 ;
      RECT 750.2500 0.0000 753.9500 0.6200 ;
      RECT 746.2500 0.0000 749.9500 0.6200 ;
      RECT 742.2500 0.0000 745.9500 0.6200 ;
      RECT 738.2500 0.0000 741.9500 0.6200 ;
      RECT 734.2500 0.0000 737.9500 0.6200 ;
      RECT 730.2500 0.0000 733.9500 0.6200 ;
      RECT 726.2500 0.0000 729.9500 0.6200 ;
      RECT 722.2500 0.0000 725.9500 0.6200 ;
      RECT 718.2500 0.0000 721.9500 0.6200 ;
      RECT 714.2500 0.0000 717.9500 0.6200 ;
      RECT 710.2500 0.0000 713.9500 0.6200 ;
      RECT 706.2500 0.0000 709.9500 0.6200 ;
      RECT 702.2500 0.0000 705.9500 0.6200 ;
      RECT 698.2500 0.0000 701.9500 0.6200 ;
      RECT 694.2500 0.0000 697.9500 0.6200 ;
      RECT 690.2500 0.0000 693.9500 0.6200 ;
      RECT 686.2500 0.0000 689.9500 0.6200 ;
      RECT 682.2500 0.0000 685.9500 0.6200 ;
      RECT 678.2500 0.0000 681.9500 0.6200 ;
      RECT 674.2500 0.0000 677.9500 0.6200 ;
      RECT 670.2500 0.0000 673.9500 0.6200 ;
      RECT 666.2500 0.0000 669.9500 0.6200 ;
      RECT 662.2500 0.0000 665.9500 0.6200 ;
      RECT 658.2500 0.0000 661.9500 0.6200 ;
      RECT 654.2500 0.0000 657.9500 0.6200 ;
      RECT 650.2500 0.0000 653.9500 0.6200 ;
      RECT 646.2500 0.0000 649.9500 0.6200 ;
      RECT 642.2500 0.0000 645.9500 0.6200 ;
      RECT 638.2500 0.0000 641.9500 0.6200 ;
      RECT 634.2500 0.0000 637.9500 0.6200 ;
      RECT 630.2500 0.0000 633.9500 0.6200 ;
      RECT 626.2500 0.0000 629.9500 0.6200 ;
      RECT 622.2500 0.0000 625.9500 0.6200 ;
      RECT 618.2500 0.0000 621.9500 0.6200 ;
      RECT 614.2500 0.0000 617.9500 0.6200 ;
      RECT 610.2500 0.0000 613.9500 0.6200 ;
      RECT 606.2500 0.0000 609.9500 0.6200 ;
      RECT 602.2500 0.0000 605.9500 0.6200 ;
      RECT 598.2500 0.0000 601.9500 0.6200 ;
      RECT 594.2500 0.0000 597.9500 0.6200 ;
      RECT 590.2500 0.0000 593.9500 0.6200 ;
      RECT 586.2500 0.0000 589.9500 0.6200 ;
      RECT 582.2500 0.0000 585.9500 0.6200 ;
      RECT 578.2500 0.0000 581.9500 0.6200 ;
      RECT 574.2500 0.0000 577.9500 0.6200 ;
      RECT 570.2500 0.0000 573.9500 0.6200 ;
      RECT 566.2500 0.0000 569.9500 0.6200 ;
      RECT 562.2500 0.0000 565.9500 0.6200 ;
      RECT 558.2500 0.0000 561.9500 0.6200 ;
      RECT 554.2500 0.0000 557.9500 0.6200 ;
      RECT 550.2500 0.0000 553.9500 0.6200 ;
      RECT 546.2500 0.0000 549.9500 0.6200 ;
      RECT 542.2500 0.0000 545.9500 0.6200 ;
      RECT 538.2500 0.0000 541.9500 0.6200 ;
      RECT 534.2500 0.0000 537.9500 0.6200 ;
      RECT 530.2500 0.0000 533.9500 0.6200 ;
      RECT 526.2500 0.0000 529.9500 0.6200 ;
      RECT 522.2500 0.0000 525.9500 0.6200 ;
      RECT 518.2500 0.0000 521.9500 0.6200 ;
      RECT 514.2500 0.0000 517.9500 0.6200 ;
      RECT 510.2500 0.0000 513.9500 0.6200 ;
      RECT 506.2500 0.0000 509.9500 0.6200 ;
      RECT 502.2500 0.0000 505.9500 0.6200 ;
      RECT 498.2500 0.0000 501.9500 0.6200 ;
      RECT 494.2500 0.0000 497.9500 0.6200 ;
      RECT 490.2500 0.0000 493.9500 0.6200 ;
      RECT 486.2500 0.0000 489.9500 0.6200 ;
      RECT 482.2500 0.0000 485.9500 0.6200 ;
      RECT 478.2500 0.0000 481.9500 0.6200 ;
      RECT 474.2500 0.0000 477.9500 0.6200 ;
      RECT 470.2500 0.0000 473.9500 0.6200 ;
      RECT 466.2500 0.0000 469.9500 0.6200 ;
      RECT 462.2500 0.0000 465.9500 0.6200 ;
      RECT 458.2500 0.0000 461.9500 0.6200 ;
      RECT 454.2500 0.0000 457.9500 0.6200 ;
      RECT 450.2500 0.0000 453.9500 0.6200 ;
      RECT 446.2500 0.0000 449.9500 0.6200 ;
      RECT 0.0000 0.0000 445.9500 0.6200 ;
  END
END core

END LIBRARY
